              <bitWidth>2</bitWidth>
            </field>
            <field>
              <name>PUPD8</name>
              <bitOffset>16</bitOffset>
              <bitWidth>2</bitWidth>
            </field>
            <field>
              <name>PUPD9</name>
              <bitOffset>18</bitOffset>
              <bitWidth>2</bitWidth>
            </field>
            <field>
              <name>PUPD10</name>
              <bitOffset>20</bitOffset>
              <bitWidth>2</bitWidth>
            </field>
            <field>
              <name>PUPD11</name>
              <bitOffset>22</bitOffset>
              <bitWidth>2</bitWidth>
            </field>
            <field>
              <name>PUPD12</name>
              <bitOffset>24</bitOffset>
              <bitWidth>2</bitWidth>
            </field>
            <field>
              <name>PUPD13</name>
              <bitOffset>26</bitOffset>
              <bitWidth>2</bitWidth>
            </field>
            <field>
              <name>PUPD14</name>
              <bitOffset>28</bitOffset>
              <bitWidth>2</bitWidth>
            </field>
            <field>
              <name>PUPD15</name>
              <bitOffset>30</bitOffset>
              <bitWidth>2</bitWidth>
            </field>
          </fields>
        </register>
        <register>
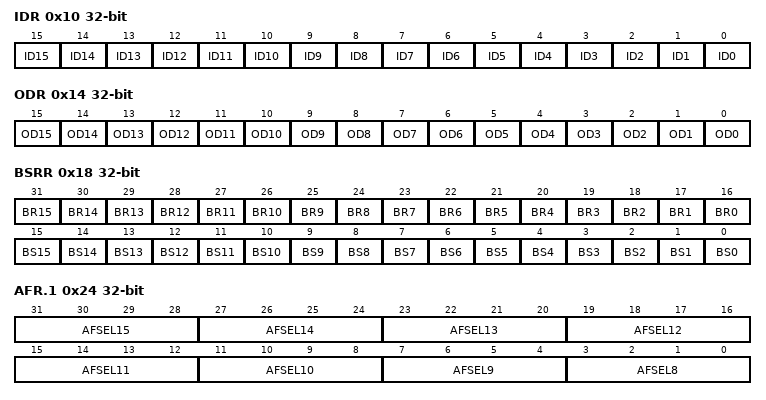
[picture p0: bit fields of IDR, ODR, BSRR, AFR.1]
          <name>IDR</name>
          <addressOffset>0x10</addressOffset>
          <size>0x20</size>
          <fields>
            <field>
              <name>ID0</name>
              <bitOffset>0</bitOffset>
              <bitWidth>1</bitWidth>
            </field>
            <field>
              <name>ID1</name>
              <bitOffset>1</bitOffset>
              <bitWidth>1</bitWidth>
            </field>
            <field>
              <name>ID2</name>
              <bitOffset>2</bitOffset>
              <bitWidth>1</bitWidth>
            </field>
            <field>
              <name>ID3</name>
              <bitOffset>3</bitOffset>
              <bitWidth>1</bitWidth>
            </field>
            <field>
              <name>ID4</name>
              <bitOffset>4</bitOffset>
              <bitWidth>1</bitWidth>
            </field>
            <field>
              <name>ID5</name>
              <bitOffset>5</bitOffset>
              <bitWidth>1</bitWidth>
            </field>
            <field>
              <name>ID6</name>
              <bitOffset>6</bitOffset>
              <bitWidth>1</bitWidth>
            </field>
            <field>
              <name>ID7</name>
              <bitOffset>7</bitOffset>
              <bitWidth>1</bitWidth>
            </field>
            <field>
              <name>ID8</name>
              <bitOffset>8</bitOffset>
              <bitWidth>1</bitWidth>
            </field>
            <field>
              <name>ID9</name>
              <bitOffset>9</bitOffset>
              <bitWidth>1</bitWidth>
            </field>
            <field>
              <name>ID10</name>
              <bitOffset>10</bitOffset>
              <bitWidth>1</bitWidth>
            </field>
            <field>
              <name>ID11</name>
              <bitOffset>11</bitOffset>
              <bitWidth>1</bitWidth>
            </field>
            <field>
              <name>ID12</name>
              <bitOffset>12</bitOffset>
              <bitWidth>1</bitWidth>
            </field>
            <field>
              <name>ID13</name>
              <bitOffset>13</bitOffset>
              <bitWidth>1</bitWidth>
            </field>
            <field>
              <name>ID14</name>
              <bitOffset>14</bitOffset>
              <bitWidth>1</bitWidth>
            </field>
            <field>
              <name>ID15</name>
              <bitOffset>15</bitOffset>
              <bitWidth>1</bitWidth>
            </field>
          </fields>
        </register>
        <register>
          <name>ODR</name>
          <addressOffset>0x14</addressOffset>
          <size>0x20</size>
          <fields>
            <field>
              <name>OD0</name>
              <bitOffset>0</bitOffset>
              <bitWidth>1</bitWidth>
            </field>
            <field>
              <name>OD1</name>
              <bitOffset>1</bitOffset>
              <bitWidth>1</bitWidth>
            </field>
            <field>
              <name>OD2</name>
              <bitOffset>2</bitOffset>
              <bitWidth>1</bitWidth>
            </field>
            <field>
              <name>OD3</name>
              <bitOffset>3</bitOffset>
              <bitWidth>1</bitWidth>
            </field>
            <field>
              <name>OD4</name>
              <bitOffset>4</bitOffset>
              <bitWidth>1</bitWidth>
            </field>
            <field>
              <name>OD5</name>
              <bitOffset>5</bitOffset>
              <bitWidth>1</bitWidth>
            </field>
            <field>
              <name>OD6</name>
              <bitOffset>6</bitOffset>
              <bitWidth>1</bitWidth>
            </field>
            <field>
              <name>OD7</name>
              <bitOffset>7</bitOffset>
              <bitWidth>1</bitWidth>
            </field>
            <field>
              <name>OD8</name>
              <bitOffset>8</bitOffset>
              <bitWidth>1</bitWidth>
            </field>
            <field>
              <name>OD9</name>
              <bitOffset>9</bitOffset>
              <bitWidth>1</bitWidth>
            </field>
            <field>
              <name>OD10</name>
              <bitOffset>10</bitOffset>
              <bitWidth>1</bitWidth>
            </field>
            <field>
              <name>OD11</name>
              <bitOffset>11</bitOffset>
              <bitWidth>1</bitWidth>
            </field>
            <field>
              <name>OD12</name>
              <bitOffset>12</bitOffset>
              <bitWidth>1</bitWidth>
            </field>
            <field>
              <name>OD13</name>
              <bitOffset>13</bitOffset>
              <bitWidth>1</bitWidth>
            </field>
            <field>
              <name>OD14</name>
              <bitOffset>14</bitOffset>
              <bitWidth>1</bitWidth>
            </field>
            <field>
              <name>OD15</name>
              <bitOffset>15</bitOffset>
              <bitWidth>1</bitWidth>
            </field>
          </fields>
        </register>
        <register>
          <name>BSRR</name>
          <addressOffset>0x18</addressOffset>
          <size>0x20</size>
          <fields>
            <field>
              <name>BS0</name>
              <bitOffset>0</bitOffset>
              <bitWidth>1</bitWidth>
            </field>
            <field>
              <name>BS1</name>
              <bitOffset>1</bitOffset>
              <bitWidth>1</bitWidth>
            </field>
            <field>
              <name>BS2</name>
              <bitOffset>2</bitOffset>
              <bitWidth>1</bitWidth>
            </field>
            <field>
              <name>BS3</name>
              <bitOffset>3</bitOffset>
              <bitWidth>1</bitWidth>
            </field>
            <field>
              <name>BS4</name>
              <bitOffset>4</bitOffset>
              <bitWidth>1</bitWidth>
            </field>
            <field>
              <name>BS5</name>
              <bitOffset>5</bitOffset>
              <bitWidth>1</bitWidth>
            </field>
            <field>
              <name>BS6</name>
              <bitOffset>6</bitOffset>
              <bitWidth>1</bitWidth>
            </field>
            <field>
              <name>BS7</name>
              <bitOffset>7</bitOffset>
              <bitWidth>1</bitWidth>
            </field>
            <field>
              <name>BS8</name>
              <bitOffset>8</bitOffset>
              <bitWidth>1</bitWidth>
            </field>
            <field>
              <name>BS9</name>
              <bitOffset>9</bitOffset>
              <bitWidth>1</bitWidth>
            </field>
            <field>
              <name>BS10</name>
              <bitOffset>10</bitOffset>
              <bitWidth>1</bitWidth>
            </field>
            <field>
              <name>BS11</name>
              <bitOffset>11</bitOffset>
              <bitWidth>1</bitWidth>
            </field>
            <field>
              <name>BS12</name>
              <bitOffset>12</bitOffset>
              <bitWidth>1</bitWidth>
            </field>
            <field>
              <name>BS13</name>
              <bitOffset>13</bitOffset>
              <bitWidth>1</bitWidth>
            </field>
            <field>
              <name>BS14</name>
              <bitOffset>14</bitOffset>
              <bitWidth>1</bitWidth>
            </field>
            <field>
              <name>BS15</name>
              <bitOffset>15</bitOffset>
              <bitWidth>1</bitWidth>
            </field>
            <field>
              <name>BR0</name>
              <bitOffset>16</bitOffset>
              <bitWidth>1</bitWidth>
            </field>
            <field>
              <name>BR1</name>
              <bitOffset>17</bitOffset>
              <bitWidth>1</bitWidth>
            </field>
            <field>
              <name>BR2</name>
              <bitOffset>18</bitOffset>
              <bitWidth>1</bitWidth>
            </field>
            <field>
              <name>BR3</name>
              <bitOffset>19</bitOffset>
              <bitWidth>1</bitWidth>
            </field>
            <field>
              <name>BR4</name>
              <bitOffset>20</bitOffset>
              <bitWidth>1</bitWidth>
            </field>
            <field>
              <name>BR5</name>
              <bitOffset>21</bitOffset>
              <bitWidth>1</bitWidth>
            </field>
            <field>
              <name>BR6</name>
              <bitOffset>22</bitOffset>
              <bitWidth>1</bitWidth>
            </field>
            <field>
              <name>BR7</name>
              <bitOffset>23</bitOffset>
              <bitWidth>1</bitWidth>
            </field>
            <field>
              <name>BR8</name>
              <bitOffset>24</bitOffset>
              <bitWidth>1</bitWidth>
            </field>
            <field>
              <name>BR9</name>
              <bitOffset>25</bitOffset>
              <bitWidth>1</bitWidth>
            </field>
            <field>
              <name>BR10</name>
              <bitOffset>26</bitOffset>
              <bitWidth>1</bitWidth>
            </field>
            <field>
              <name>BR11</name>
              <bitOffset>27</bitOffset>
              <bitWidth>1</bitWidth>
            </field>
            <field>
              <name>BR12</name>
              <bitOffset>28</bitOffset>
              <bitWidth>1</bitWidth>
            </field>
            <field>
              <name>BR13</name>
              <bitOffset>29</bitOffset>
              <bitWidth>1</bitWidth>
            </field>
            <field>
              <name>BR14</name>
              <bitOffset>30</bitOffset>
              <bitWidth>1</bitWidth>
            </field>
            <field>
              <name>BR15</name>
              <bitOffset>31</bitOffset>
              <bitWidth>1</bitWidth>
            </field>
          </fields>
        </register>
        <register>
          <name>LCKR</name>
          <addressOffset>0x1c</addressOffset>
          <size>0x20</size>
        </register>
        <register>
          <name>AFR.0</name>
          <addressOffset>0x20</addressOffset>
          <size>0x20</size>
        </register>
        <register>
          <name>AFR.1</name>
          <addressOffset>0x24</addressOffset>
          <size>0x20</size>
          <fields>
            <field>
              <name>AFSEL8</name>
              <bitOffset>0</bitOffset>
              <bitWidth>4</bitWidth>
            </field>
            <field>
              <name>AFSEL9</name>
              <bitOffset>4</bitOffset>
              <bitWidth>4</bitWidth>
            </field>
            <field>
              <name>AFSEL10</name>
              <bitOffset>8</bitOffset>
              <bitWidth>4</bitWidth>
            </field>
            <field>
              <name>AFSEL11</name>
              <bitOffset>12</bitOffset>
              <bitWidth>4</bitWidth>
            </field>
            <field>
              <name>AFSEL12</name>
              <bitOffset>16</bitOffset>
              <bitWidth>4</bitWidth>
            </field>
            <field>
              <name>AFSEL13</name>
              <bitOffset>20</bitOffset>
              <bitWidth>4</bitWidth>
            </field>
            <field>
              <name>AFSEL14</name>
              <bitOffset>24</bitOffset>
              <bitWidth>4</bitWidth>
            </field>
            <field>
              <name>AFSEL15</name>
              <bitOffset>28</bitOffset>
              <bitWidth>4</bitWidth>
            </field>
          </fields>
        </register>
      </registers>
    </peripheral>
    <peripheral>
      <name>GPIOH</name>
      <baseAddress>0x40021c00</baseAddress>
      <registers>
        <register>
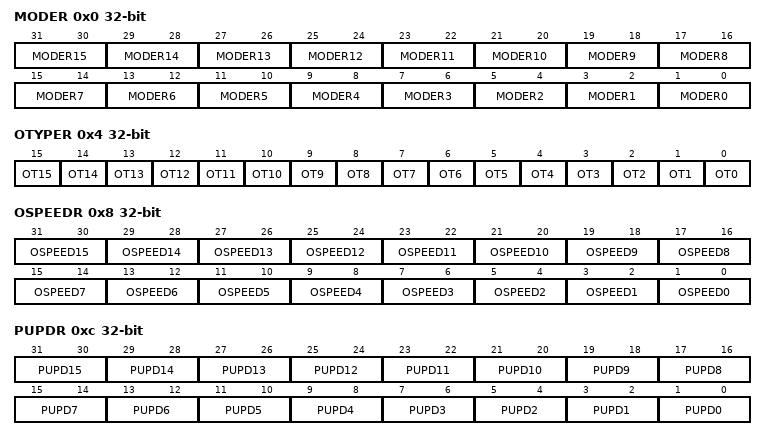
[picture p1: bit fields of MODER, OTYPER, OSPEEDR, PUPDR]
          <name>MODER</name>
          <addressOffset>0x0</addressOffset>
          <size>0x20</size>
          <fields>
            <field>
              <name>MODER0</name>
              <bitOffset>0</bitOffset>
              <bitWidth>2</bitWidth>
            </field>
            <field>
              <name>MODER1</name>
              <bitOffset>2</bitOffset>
              <bitWidth>2</bitWidth>
            </field>
            <field>
              <name>MODER2</name>
              <bitOffset>4</bitOffset>
              <bitWidth>2</bitWidth>
            </field>
            <field>
              <name>MODER3</name>
              <bitOffset>6</bitOffset>
              <bitWidth>2</bitWidth>
            </field>
            <field>
              <name>MODER4</name>
              <bitOffset>8</bitOffset>
              <bitWidth>2</bitWidth>
            </field>
            <field>
              <name>MODER5</name>
              <bitOffset>10</bitOffset>
              <bitWidth>2</bitWidth>
            </field>
            <field>
              <name>MODER6</name>
              <bitOffset>12</bitOffset>
              <bitWidth>2</bitWidth>
            </field>
            <field>
              <name>MODER7</name>
              <bitOffset>14</bitOffset>
              <bitWidth>2</bitWidth>
            </field>
            <field>
              <name>MODER8</name>
              <bitOffset>16</bitOffset>
              <bitWidth>2</bitWidth>
            </field>
            <field>
              <name>MODER9</name>
              <bitOffset>18</bitOffset>
              <bitWidth>2</bitWidth>
            </field>
            <field>
              <name>MODER10</name>
              <bitOffset>20</bitOffset>
              <bitWidth>2</bitWidth>
            </field>
            <field>
              <name>MODER11</name>
              <bitOffset>22</bitOffset>
              <bitWidth>2</bitWidth>
            </field>
            <field>
              <name>MODER12</name>
              <bitOffset>24</bitOffset>
              <bitWidth>2</bitWidth>
            </field>
            <field>
              <name>MODER13</name>
              <bitOffset>26</bitOffset>
              <bitWidth>2</bitWidth>
            </field>
            <field>
              <name>MODER14</name>
              <bitOffset>28</bitOffset>
              <bitWidth>2</bitWidth>
            </field>
            <field>
              <name>MODER15</name>
              <bitOffset>30</bitOffset>
              <bitWidth>2</bitWidth>
            </field>
          </fields>
        </register>
        <register>
          <name>OTYPER</name>
          <addressOffset>0x4</addressOffset>
          <size>0x20</size>
          <fields>
            <field>
              <name>OT0</name>
              <bitOffset>0</bitOffset>
              <bitWidth>1</bitWidth>
            </field>
            <field>
              <name>OT1</name>
              <bitOffset>1</bitOffset>
              <bitWidth>1</bitWidth>
            </field>
            <field>
              <name>OT2</name>
              <bitOffset>2</bitOffset>
              <bitWidth>1</bitWidth>
            </field>
            <field>
              <name>OT3</name>
              <bitOffset>3</bitOffset>
              <bitWidth>1</bitWidth>
            </field>
            <field>
              <name>OT4</name>
              <bitOffset>4</bitOffset>
              <bitWidth>1</bitWidth>
            </field>
            <field>
              <name>OT5</name>
              <bitOffset>5</bitOffset>
              <bitWidth>1</bitWidth>
            </field>
            <field>
              <name>OT6</name>
              <bitOffset>6</bitOffset>
              <bitWidth>1</bitWidth>
            </field>
            <field>
              <name>OT7</name>
              <bitOffset>7</bitOffset>
              <bitWidth>1</bitWidth>
            </field>
            <field>
              <name>OT8</name>
              <bitOffset>8</bitOffset>
              <bitWidth>1</bitWidth>
            </field>
            <field>
              <name>OT9</name>
              <bitOffset>9</bitOffset>
              <bitWidth>1</bitWidth>
            </field>
            <field>
              <name>OT10</name>
              <bitOffset>10</bitOffset>
              <bitWidth>1</bitWidth>
            </field>
            <field>
              <name>OT11</name>
              <bitOffset>11</bitOffset>
              <bitWidth>1</bitWidth>
            </field>
            <field>
              <name>OT12</name>
              <bitOffset>12</bitOffset>
              <bitWidth>1</bitWidth>
            </field>
            <field>
              <name>OT13</name>
              <bitOffset>13</bitOffset>
              <bitWidth>1</bitWidth>
            </field>
            <field>
              <name>OT14</name>
              <bitOffset>14</bitOffset>
              <bitWidth>1</bitWidth>
            </field>
            <field>
              <name>OT15</name>
              <bitOffset>15</bitOffset>
              <bitWidth>1</bitWidth>
            </field>
          </fields>
        </register>
        <register>
          <name>OSPEEDR</name>
          <addressOffset>0x8</addressOffset>
          <size>0x20</size>
          <fields>
            <field>
              <name>OSPEED0</name>
              <bitOffset>0</bitOffset>
              <bitWidth>2</bitWidth>
            </field>
            <field>
              <name>OSPEED1</name>
              <bitOffset>2</bitOffset>
              <bitWidth>2</bitWidth>
            </field>
            <field>
              <name>OSPEED2</name>
              <bitOffset>4</bitOffset>
              <bitWidth>2</bitWidth>
            </field>
            <field>
              <name>OSPEED3</name>
              <bitOffset>6</bitOffset>
              <bitWidth>2</bitWidth>
            </field>
            <field>
              <name>OSPEED4</name>
              <bitOffset>8</bitOffset>
              <bitWidth>2</bitWidth>
            </field>
            <field>
              <name>OSPEED5</name>
              <bitOffset>10</bitOffset>
              <bitWidth>2</bitWidth>
            </field>
            <field>
              <name>OSPEED6</name>
              <bitOffset>12</bitOffset>
              <bitWidth>2</bitWidth>
            </field>
            <field>
              <name>OSPEED7</name>
              <bitOffset>14</bitOffset>
              <bitWidth>2</bitWidth>
            </field>
            <field>
              <name>OSPEED8</name>
              <bitOffset>16</bitOffset>
              <bitWidth>2</bitWidth>
            </field>
            <field>
              <name>OSPEED9</name>
              <bitOffset>18</bitOffset>
              <bitWidth>2</bitWidth>
            </field>
            <field>
              <name>OSPEED10</name>
              <bitOffset>20</bitOffset>
              <bitWidth>2</bitWidth>
            </field>
            <field>
              <name>OSPEED11</name>
              <bitOffset>22</bitOffset>
              <bitWidth>2</bitWidth>
            </field>
            <field>
              <name>OSPEED12</name>
              <bitOffset>24</bitOffset>
              <bitWidth>2</bitWidth>
            </field>
            <field>
              <name>OSPEED13</name>
              <bitOffset>26</bitOffset>
              <bitWidth>2</bitWidth>
            </field>
            <field>
              <name>OSPEED14</name>
              <bitOffset>28</bitOffset>
              <bitWidth>2</bitWidth>
            </field>
            <field>
              <name>OSPEED15</name>
              <bitOffset>30</bitOffset>
              <bitWidth>2</bitWidth>
            </field>
          </fields>
        </register>
        <register>
          <name>PUPDR</name>
          <addressOffset>0xc</addressOffset>
          <size>0x20</size>
          <fields>
            <field>
              <name>PUPD0</name>
              <bitOffset>0</bitOffset>
              <bitWidth>2</bitWidth>
            </field>
            <field>
              <name>PUPD1</name>
              <bitOffset>2</bitOffset>
              <bitWidth>2</bitWidth>
            </field>
            <field>
              <name>PUPD2</name>
              <bitOffset>4</bitOffset>
              <bitWidth>2</bitWidth>
            </field>
            <field>
              <name>PUPD3</name>
              <bitOffset>6</bitOffset>
              <bitWidth>2</bitWidth>
            </field>
            <field>
              <name>PUPD4</name>
              <bitOffset>8</bitOffset>
              <bitWidth>2</bitWidth>
            </field>
            <field>
              <name>PUPD5</name>
              <bitOffset>10</bitOffset>
              <bitWidth>2</bitWidth>
            </field>
            <field>
              <name>PUPD6</name>
              <bitOffset>12</bitOffset>
              <bitWidth>2</bitWidth>
            </field>
            <field>
              <name>PUPD7</name>
              <bitOffset>14</bitOffset>
              <bitWidth>2</bitWidth>
            </field>
            <field>
              <name>PUPD8</name>
              <bitOffset>16</bitOffset>
              <bitWidth>2</bitWidth>
            </field>
            <field>
              <name>PUPD9</name>
              <bitOffset>18</bitOffset>
              <bitWidth>2</bitWidth>
            </field>
            <field>
              <name>PUPD10</name>
              <bitOffset>20</bitOffset>
              <bitWidth>2</bitWidth>
            </field>
            <field>
              <name>PUPD11</name>
              <bitOffset>22</bitOffset>
              <bitWidth>2</bitWidth>
            </field>
            <field>
              <name>PUPD12</name>
              <bitOffset>24</bitOffset>
              <bitWidth>2</bitWidth>
            </field>
            <field>
              <name>PUPD13</name>
              <bitOffset>26</bitOffset>
              <bitWidth>2</bitWidth>
            </field>
            <field>
              <name>PUPD14</name>
              <bitOffset>28</bitOffset>
              <bitWidth>2</bitWidth>
            </field>
            <field>
              <name>PUPD15</name>
              <bitOffset>30</bitOffset>
              <bitWidth>2</bitWidth>
            </field>
          </fields>
        </register>
        <register>
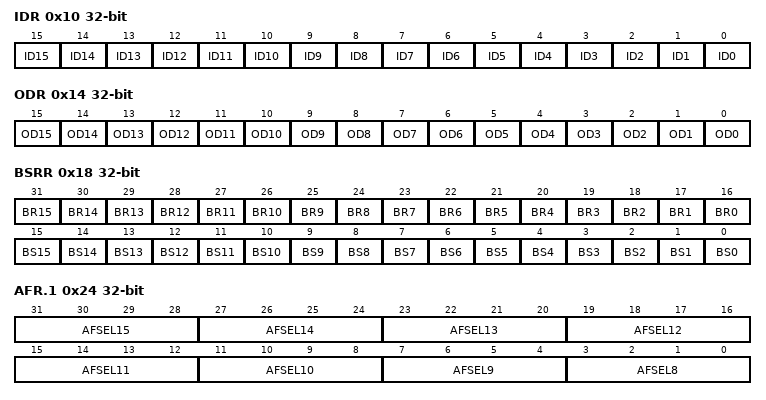
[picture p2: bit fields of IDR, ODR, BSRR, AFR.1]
          <name>IDR</name>
          <addressOffset>0x10</addressOffset>
          <size>0x20</size>
          <fields>
            <field>
              <name>ID0</name>
              <bitOffset>0</bitOffset>
              <bitWidth>1</bitWidth>
            </field>
            <field>
              <name>ID1</name>
              <bitOffset>1</bitOffset>
              <bitWidth>1</bitWidth>
            </field>
            <field>
              <name>ID2</name>
              <bitOffset>2</bitOffset>
              <bitWidth>1</bitWidth>
            </field>
            <field>
              <name>ID3</name>
              <bitOffset>3</bitOffset>
              <bitWidth>1</bitWidth>
            </field>
            <field>
              <name>ID4</name>
              <bitOffset>4</bitOffset>
              <bitWidth>1</bitWidth>
            </field>
            <field>
              <name>ID5</name>
              <bitOffset>5</bitOffset>
              <bitWidth>1</bitWidth>
            </field>
            <field>
              <name>ID6</name>
              <bitOffset>6</bitOffset>
              <bitWidth>1</bitWidth>
            </field>
            <field>
              <name>ID7</name>
              <bitOffset>7</bitOffset>
              <bitWidth>1</bitWidth>
            </field>
            <field>
              <name>ID8</name>
              <bitOffset>8</bitOffset>
              <bitWidth>1</bitWidth>
            </field>
            <field>
              <name>ID9</name>
              <bitOffset>9</bitOffset>
              <bitWidth>1</bitWidth>
            </field>
            <field>
              <name>ID10</name>
              <bitOffset>10</bitOffset>
              <bitWidth>1</bitWidth>
            </field>
            <field>
              <name>ID11</name>
              <bitOffset>11</bitOffset>
              <bitWidth>1</bitWidth>
            </field>
            <field>
              <name>ID12</name>
              <bitOffset>12</bitOffset>
              <bitWidth>1</bitWidth>
            </field>
            <field>
              <name>ID13</name>
              <bitOffset>13</bitOffset>
              <bitWidth>1</bitWidth>
            </field>
            <field>
              <name>ID14</name>
              <bitOffset>14</bitOffset>
              <bitWidth>1</bitWidth>
            </field>
            <field>
              <name>ID15</name>
              <bitOffset>15</bitOffset>
              <bitWidth>1</bitWidth>
            </field>
          </fields>
        </register>
        <register>
          <name>ODR</name>
          <addressOffset>0x14</addressOffset>
          <size>0x20</size>
          <fields>
            <field>
              <name>OD0</name>
              <bitOffset>0</bitOffset>
              <bitWidth>1</bitWidth>
            </field>
            <field>
              <name>OD1</name>
              <bitOffset>1</bitOffset>
              <bitWidth>1</bitWidth>
            </field>
            <field>
              <name>OD2</name>
              <bitOffset>2</bitOffset>
              <bitWidth>1</bitWidth>
            </field>
            <field>
              <name>OD3</name>
              <bitOffset>3</bitOffset>
              <bitWidth>1</bitWidth>
            </field>
            <field>
              <name>OD4</name>
              <bitOffset>4</bitOffset>
              <bitWidth>1</bitWidth>
            </field>
            <field>
              <name>OD5</name>
              <bitOffset>5</bitOffset>
              <bitWidth>1</bitWidth>
            </field>
            <field>
              <name>OD6</name>
              <bitOffset>6</bitOffset>
              <bitWidth>1</bitWidth>
            </field>
            <field>
              <name>OD7</name>
              <bitOffset>7</bitOffset>
              <bitWidth>1</bitWidth>
            </field>
            <field>
              <name>OD8</name>
              <bitOffset>8</bitOffset>
              <bitWidth>1</bitWidth>
            </field>
            <field>
              <name>OD9</name>
              <bitOffset>9</bitOffset>
              <bitWidth>1</bitWidth>
            </field>
            <field>
              <name>OD10</name>
              <bitOffset>10</bitOffset>
              <bitWidth>1</bitWidth>
            </field>
            <field>
              <name>OD11</name>
              <bitOffset>11</bitOffset>
              <bitWidth>1</bitWidth>
            </field>
            <field>
              <name>OD12</name>
              <bitOffset>12</bitOffset>
              <bitWidth>1</bitWidth>
            </field>
            <field>
              <name>OD13</name>
              <bitOffset>13</bitOffset>
              <bitWidth>1</bitWidth>
            </field>
            <field>
              <name>OD14</name>
              <bitOffset>14</bitOffset>
              <bitWidth>1</bitWidth>
            </field>
            <field>
              <name>OD15</name>
              <bitOffset>15</bitOffset>
              <bitWidth>1</bitWidth>
            </field>
          </fields>
        </register>
        <register>
          <name>BSRR</name>
          <addressOffset>0x18</addressOffset>
          <size>0x20</size>
          <fields>
            <field>
              <name>BS0</name>
              <bitOffset>0</bitOffset>
              <bitWidth>1</bitWidth>
            </field>
            <field>
              <name>BS1</name>
              <bitOffset>1</bitOffset>
              <bitWidth>1</bitWidth>
            </field>
            <field>
              <name>BS2</name>
              <bitOffset>2</bitOffset>
              <bitWidth>1</bitWidth>
            </field>
            <field>
              <name>BS3</name>
              <bitOffset>3</bitOffset>
              <bitWidth>1</bitWidth>
            </field>
            <field>
              <name>BS4</name>
              <bitOffset>4</bitOffset>
              <bitWidth>1</bitWidth>
            </field>
            <field>
              <name>BS5</name>
              <bitOffset>5</bitOffset>
              <bitWidth>1</bitWidth>
            </field>
            <field>
              <name>BS6</name>
              <bitOffset>6</bitOffset>
              <bitWidth>1</bitWidth>
            </field>
            <field>
              <name>BS7</name>
              <bitOffset>7</bitOffset>
              <bitWidth>1</bitWidth>
            </field>
            <field>
              <name>BS8</name>
              <bitOffset>8</bitOffset>
              <bitWidth>1</bitWidth>
            </field>
            <field>
              <name>BS9</name>
              <bitOffset>9</bitOffset>
              <bitWidth>1</bitWidth>
            </field>
            <field>
              <name>BS10</name>
              <bitOffset>10</bitOffset>
              <bitWidth>1</bitWidth>
            </field>
            <field>
              <name>BS11</name>
              <bitOffset>11</bitOffset>
              <bitWidth>1</bitWidth>
            </field>
            <field>
              <name>BS12</name>
              <bitOffset>12</bitOffset>
              <bitWidth>1</bitWidth>
            </field>
            <field>
              <name>BS13</name>
              <bitOffset>13</bitOffset>
              <bitWidth>1</bitWidth>
            </field>
            <field>
              <name>BS14</name>
              <bitOffset>14</bitOffset>
              <bitWidth>1</bitWidth>
            </field>
            <field>
              <name>BS15</name>
              <bitOffset>15</bitOffset>
              <bitWidth>1</bitWidth>
            </field>
            <field>
              <name>BR0</name>
              <bitOffset>16</bitOffset>
              <bitWidth>1</bitWidth>
            </field>
            <field>
              <name>BR1</name>
              <bitOffset>17</bitOffset>
              <bitWidth>1</bitWidth>
            </field>
            <field>
              <name>BR2</name>
              <bitOffset>18</bitOffset>
              <bitWidth>1</bitWidth>
            </field>
            <field>
              <name>BR3</name>
              <bitOffset>19</bitOffset>
              <bitWidth>1</bitWidth>
            </field>
            <field>
              <name>BR4</name>
              <bitOffset>20</bitOffset>
              <bitWidth>1</bitWidth>
            </field>
            <field>
              <name>BR5</name>
              <bitOffset>21</bitOffset>
              <bitWidth>1</bitWidth>
            </field>
            <field>
              <name>BR6</name>
              <bitOffset>22</bitOffset>
              <bitWidth>1</bitWidth>
            </field>
            <field>
              <name>BR7</name>
              <bitOffset>23</bitOffset>
              <bitWidth>1</bitWidth>
            </field>
            <field>
              <name>BR8</name>
              <bitOffset>24</bitOffset>
              <bitWidth>1</bitWidth>
            </field>
            <field>
              <name>BR9</name>
              <bitOffset>25</bitOffset>
              <bitWidth>1</bitWidth>
            </field>
            <field>
              <name>BR10</name>
              <bitOffset>26</bitOffset>
              <bitWidth>1</bitWidth>
            </field>
            <field>
              <name>BR11</name>
              <bitOffset>27</bitOffset>
              <bitWidth>1</bitWidth>
            </field>
            <field>
              <name>BR12</name>
              <bitOffset>28</bitOffset>
              <bitWidth>1</bitWidth>
            </field>
            <field>
              <name>BR13</name>
              <bitOffset>29</bitOffset>
              <bitWidth>1</bitWidth>
            </field>
            <field>
              <name>BR14</name>
              <bitOffset>30</bitOffset>
              <bitWidth>1</bitWidth>
            </field>
            <field>
              <name>BR15</name>
              <bitOffset>31</bitOffset>
              <bitWidth>1</bitWidth>
            </field>
          </fields>
        </register>
        <register>
          <name>LCKR</name>
          <addressOffset>0x1c</addressOffset>
          <size>0x20</size>
        </register>
        <register>
          <name>AFR.0</name>
          <addressOffset>0x20</addressOffset>
          <size>0x20</size>
        </register>
        <register>
          <name>AFR.1</name>
          <addressOffset>0x24</addressOffset>
          <size>0x20</size>
          <fields>
            <field>
              <name>AFSEL8</name>
              <bitOffset>0</bitOffset>
              <bitWidth>4</bitWidth>
            </field>
            <field>
              <name>AFSEL9</name>
              <bitOffset>4</bitOffset>
              <bitWidth>4</bitWidth>
            </field>
            <field>
              <name>AFSEL10</name>
              <bitOffset>8</bitOffset>
              <bitWidth>4</bitWidth>
            </field>
            <field>
              <name>AFSEL11</name>
              <bitOffset>12</bitOffset>
              <bitWidth>4</bitWidth>
            </field>
            <field>
              <name>AFSEL12</name>
              <bitOffset>16</bitOffset>
              <bitWidth>4</bitWidth>
            </field>
            <field>
              <name>AFSEL13</name>
              <bitOffset>20</bitOffset>
              <bitWidth>4</bitWidth>
            </field>
            <field>
              <name>AFSEL14</name>
              <bitOffset>24</bitOffset>
              <bitWidth>4</bitWidth>
            </field>
            <field>
              <name>AFSEL15</name>
              <bitOffset>28</bitOffset>
              <bitWidth>4</bitWidth>
            </field>
          </fields>
        </register>
      </registers>
    </peripheral>
    <peripheral>
      <name>CRC</name>
      <baseAddress>0x40023000</baseAddress>
      <registers>
        <register>
          <name>DR</name>
          <addressOffset>0x0</addressOffset>
          <size>0x20</size>
          <fields>
            <field>
              <name>DR</name>
              <bitOffset>0</bitOffset>
              <bitWidth>32</bitWidth>
            </field>
          </fields>
        </register>
        <register>
          <name>IDR</name>
          <addressOffset>0x4</addressOffset>
          <size>0x8</size>
          <fields>
            <field>
              <name>IDR</name>
              <bitOffset>0</bitOffset>
              <bitWidth>8</bitWidth>
            </field>
          </fields>
        </register>
        <register>
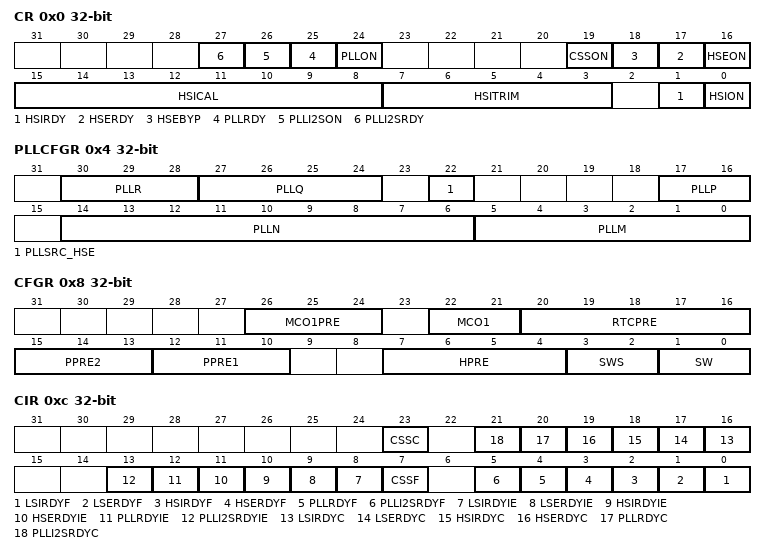
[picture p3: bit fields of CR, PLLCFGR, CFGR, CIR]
          <name>CR</name>
          <addressOffset>0x8</addressOffset>
          <size>0x20</size>
          <fields>
            <field>
              <name>RESET</name>
              <bitOffset>0</bitOffset>
              <bitWidth>1</bitWidth>
            </field>
          </fields>
        </register>
      </registers>
    </peripheral>
    <peripheral>
      <name>RCC</name>
      <baseAddress>0x40023800</baseAddress>
      <registers>
        <register>
          <name>CR</name>
          <addressOffset>0x0</addressOffset>
          <size>0x20</size>
          <fields>
            <field>
              <name>HSION</name>
              <bitOffset>0</bitOffset>
              <bitWidth>1</bitWidth>
            </field>
            <field>
              <name>HSIRDY</name>
              <bitOffset>1</bitOffset>
              <bitWidth>1</bitWidth>
            </field>
            <field>
              <name>HSITRIM</name>
              <bitOffset>3</bitOffset>
              <bitWidth>5</bitWidth>
            </field>
            <field>
              <name>HSICAL</name>
              <bitOffset>8</bitOffset>
              <bitWidth>8</bitWidth>
            </field>
            <field>
              <name>HSEON</name>
              <bitOffset>16</bitOffset>
              <bitWidth>1</bitWidth>
            </field>
            <field>
              <name>HSERDY</name>
              <bitOffset>17</bitOffset>
              <bitWidth>1</bitWidth>
            </field>
            <field>
              <name>HSEBYP</name>
              <bitOffset>18</bitOffset>
              <bitWidth>1</bitWidth>
            </field>
            <field>
              <name>CSSON</name>
              <bitOffset>19</bitOffset>
              <bitWidth>1</bitWidth>
            </field>
            <field>
              <name>PLLON</name>
              <bitOffset>24</bitOffset>
              <bitWidth>1</bitWidth>
            </field>
            <field>
              <name>PLLRDY</name>
              <bitOffset>25</bitOffset>
              <bitWidth>1</bitWidth>
            </field>
            <field>
              <name>PLLI2SON</name>
              <bitOffset>26</bitOffset>
              <bitWidth>1</bitWidth>
            </field>
            <field>
              <name>PLLI2SRDY</name>
              <bitOffset>27</bitOffset>
              <bitWidth>1</bitWidth>
            </field>
          </fields>
        </register>
        <register>
          <name>PLLCFGR</name>
          <addressOffset>0x4</addressOffset>
          <size>0x20</size>
          <fields>
            <field>
              <name>PLLM</name>
              <bitOffset>0</bitOffset>
              <bitWidth>6</bitWidth>
            </field>
            <field>
              <name>PLLN</name>
              <bitOffset>6</bitOffset>
              <bitWidth>9</bitWidth>
            </field>
            <field>
              <name>PLLP</name>
              <bitOffset>16</bitOffset>
              <bitWidth>2</bitWidth>
            </field>
            <field>
              <name>PLLSRC_HSE</name>
              <bitOffset>22</bitOffset>
              <bitWidth>1</bitWidth>
            </field>
            <field>
              <name>PLLQ</name>
              <bitOffset>24</bitOffset>
              <bitWidth>4</bitWidth>
            </field>
            <field>
              <name>PLLR</name>
              <bitOffset>28</bitOffset>
              <bitWidth>3</bitWidth>
            </field>
          </fields>
        </register>
        <register>
          <name>CFGR</name>
          <addressOffset>0x8</addressOffset>
          <size>0x20</size>
          <fields>
            <field>
              <name>SW</name>
              <bitOffset>0</bitOffset>
              <bitWidth>2</bitWidth>
            </field>
            <field>
              <name>SWS</name>
              <bitOffset>2</bitOffset>
              <bitWidth>2</bitWidth>
            </field>
            <field>
              <name>HPRE</name>
              <bitOffset>4</bitOffset>
              <bitWidth>4</bitWidth>
            </field>
            <field>
              <name>PPRE1</name>
              <bitOffset>10</bitOffset>
              <bitWidth>3</bitWidth>
            </field>
            <field>
              <name>PPRE2</name>
              <bitOffset>13</bitOffset>
              <bitWidth>3</bitWidth>
            </field>
            <field>
              <name>RTCPRE</name>
              <bitOffset>16</bitOffset>
              <bitWidth>5</bitWidth>
            </field>
            <field>
              <name>MCO1</name>
              <bitOffset>21</bitOffset>
              <bitWidth>2</bitWidth>
            </field>
            <field>
              <name>MCO1PRE</name>
              <bitOffset>24</bitOffset>
              <bitWidth>3</bitWidth>
            </field>
          </fields>
        </register>
        <register>
          <name>CIR</name>
          <addressOffset>0xc</addressOffset>
          <size>0x20</size>
          <fields>
            <field>
              <name>LSIRDYF</name>
              <bitOffset>0</bitOffset>
              <bitWidth>1</bitWidth>
            </field>
            <field>
              <name>LSERDYF</name>
              <bitOffset>1</bitOffset>
              <bitWidth>1</bitWidth>
            </field>
            <field>
              <name>HSIRDYF</name>
              <bitOffset>2</bitOffset>
              <bitWidth>1</bitWidth>
            </field>
            <field>
              <name>HSERDYF</name>
              <bitOffset>3</bitOffset>
              <bitWidth>1</bitWidth>
            </field>
            <field>
              <name>PLLRDYF</name>
              <bitOffset>4</bitOffset>
              <bitWidth>1</bitWidth>
            </field>
            <field>
              <name>PLLI2SRDYF</name>
              <bitOffset>5</bitOffset>
              <bitWidth>1</bitWidth>
            </field>
            <field>
              <name>CSSF</name>
              <bitOffset>7</bitOffset>
              <bitWidth>1</bitWidth>
            </field>
            <field>
              <name>LSIRDYIE</name>
              <bitOffset>8</bitOffset>
              <bitWidth>1</bitWidth>
            </field>
            <field>
              <name>LSERDYIE</name>
              <bitOffset>9</bitOffset>
              <bitWidth>1</bitWidth>
            </field>
            <field>
              <name>HSIRDYIE</name>
              <bitOffset>10</bitOffset>
              <bitWidth>1</bitWidth>
            </field>
            <field>
              <name>HSERDYIE</name>
              <bitOffset>11</bitOffset>
              <bitWidth>1</bitWidth>
            </field>
            <field>
              <name>PLLRDYIE</name>
              <bitOffset>12</bitOffset>
              <bitWidth>1</bitWidth>
            </field>
            <field>
              <name>PLLI2SRDYIE</name>
              <bitOffset>13</bitOffset>
              <bitWidth>1</bitWidth>
            </field>
            <field>
              <name>LSIRDYC</name>
              <bitOffset>16</bitOffset>
              <bitWidth>1</bitWidth>
            </field>
            <field>
              <name>LSERDYC</name>
              <bitOffset>17</bitOffset>
              <bitWidth>1</bitWidth>
            </field>
            <field>
              <name>HSIRDYC</name>
              <bitOffset>18</bitOffset>
              <bitWidth>1</bitWidth>
            </field>
            <field>
              <name>HSERDYC</name>
              <bitOffset>19</bitOffset>
              <bitWidth>1</bitWidth>
            </field>
            <field>
              <name>PLLRDYC</name>
              <bitOffset>20</bitOffset>
              <bitWidth>1</bitWidth>
            </field>
            <field>
              <name>PLLI2SRDYC</name>
              <bitOffset>21</bitOffset>
              <bitWidth>1</bitWidth>
            </field>
            <field>
              <name>CSSC</name>
              <bitOffset>23</bitOffset>
              <bitWidth>1</bitWidth>
            </field>
          </fields>
        </register>
        <register>
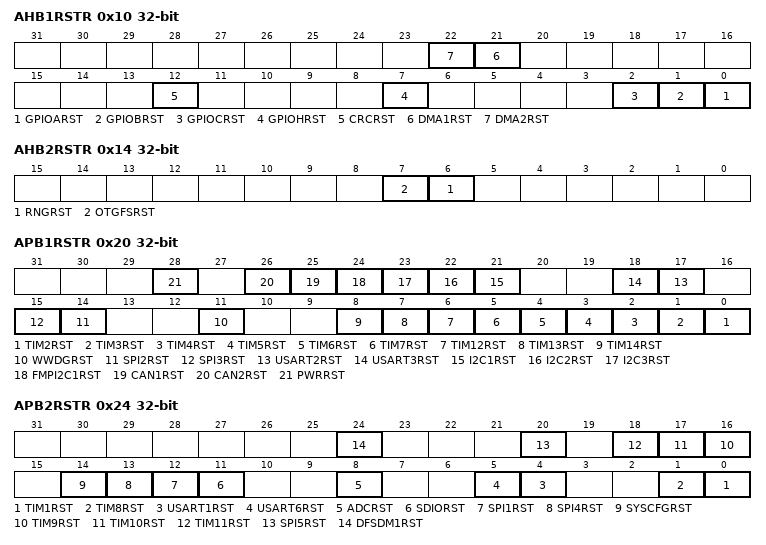
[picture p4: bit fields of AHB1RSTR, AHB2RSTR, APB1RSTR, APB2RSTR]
          <name>AHB1RSTR</name>
          <addressOffset>0x10</addressOffset>
          <size>0x20</size>
          <fields>
            <field>
              <name>GPIOARST</name>
              <bitOffset>0</bitOffset>
              <bitWidth>1</bitWidth>
            </field>
            <field>
              <name>GPIOBRST</name>
              <bitOffset>1</bitOffset>
              <bitWidth>1</bitWidth>
            </field>
            <field>
              <name>GPIOCRST</name>
              <bitOffset>2</bitOffset>
              <bitWidth>1</bitWidth>
            </field>
            <field>
              <name>GPIOHRST</name>
              <bitOffset>7</bitOffset>
              <bitWidth>1</bitWidth>
            </field>
            <field>
              <name>CRCRST</name>
              <bitOffset>12</bitOffset>
              <bitWidth>1</bitWidth>
            </field>
            <field>
              <name>DMA1RST</name>
              <bitOffset>21</bitOffset>
              <bitWidth>1</bitWidth>
            </field>
            <field>
              <name>DMA2RST</name>
              <bitOffset>22</bitOffset>
              <bitWidth>1</bitWidth>
            </field>
          </fields>
        </register>
        <register>
          <name>AHB2RSTR</name>
          <addressOffset>0x14</addressOffset>
          <size>0x20</size>
          <fields>
            <field>
              <name>RNGRST</name>
              <bitOffset>6</bitOffset>
              <bitWidth>1</bitWidth>
            </field>
            <field>
              <name>OTGFSRST</name>
              <bitOffset>7</bitOffset>
              <bitWidth>1</bitWidth>
            </field>
          </fields>
        </register>
        <register>
          <name>APB1RSTR</name>
          <addressOffset>0x20</addressOffset>
          <size>0x20</size>
          <fields>
            <field>
              <name>TIM2RST</name>
              <bitOffset>0</bitOffset>
              <bitWidth>1</bitWidth>
            </field>
            <field>
              <name>TIM3RST</name>
              <bitOffset>1</bitOffset>
              <bitWidth>1</bitWidth>
            </field>
            <field>
              <name>TIM4RST</name>
              <bitOffset>2</bitOffset>
              <bitWidth>1</bitWidth>
            </field>
            <field>
              <name>TIM5RST</name>
              <bitOffset>3</bitOffset>
              <bitWidth>1</bitWidth>
            </field>
            <field>
              <name>TIM6RST</name>
              <bitOffset>4</bitOffset>
              <bitWidth>1</bitWidth>
            </field>
            <field>
              <name>TIM7RST</name>
              <bitOffset>5</bitOffset>
              <bitWidth>1</bitWidth>
            </field>
            <field>
              <name>TIM12RST</name>
              <bitOffset>6</bitOffset>
              <bitWidth>1</bitWidth>
            </field>
            <field>
              <name>TIM13RST</name>
              <bitOffset>7</bitOffset>
              <bitWidth>1</bitWidth>
            </field>
            <field>
              <name>TIM14RST</name>
              <bitOffset>8</bitOffset>
              <bitWidth>1</bitWidth>
            </field>
            <field>
              <name>WWDGRST</name>
              <bitOffset>11</bitOffset>
              <bitWidth>1</bitWidth>
            </field>
            <field>
              <name>SPI2RST</name>
              <bitOffset>14</bitOffset>
              <bitWidth>1</bitWidth>
            </field>
            <field>
              <name>SPI3RST</name>
              <bitOffset>15</bitOffset>
              <bitWidth>1</bitWidth>
            </field>
            <field>
              <name>USART2RST</name>
              <bitOffset>17</bitOffset>
              <bitWidth>1</bitWidth>
            </field>
            <field>
              <name>USART3RST</name>
              <bitOffset>18</bitOffset>
              <bitWidth>1</bitWidth>
            </field>
            <field>
              <name>I2C1RST</name>
              <bitOffset>21</bitOffset>
              <bitWidth>1</bitWidth>
            </field>
            <field>
              <name>I2C2RST</name>
              <bitOffset>22</bitOffset>
              <bitWidth>1</bitWidth>
            </field>
            <field>
              <name>I2C3RST</name>
              <bitOffset>23</bitOffset>
              <bitWidth>1</bitWidth>
            </field>
            <field>
              <name>FMPI2C1RST</name>
              <bitOffset>24</bitOffset>
              <bitWidth>1</bitWidth>
            </field>
            <field>
              <name>CAN1RST</name>
              <bitOffset>25</bitOffset>
              <bitWidth>1</bitWidth>
            </field>
            <field>
              <name>CAN2RST</name>
              <bitOffset>26</bitOffset>
              <bitWidth>1</bitWidth>
            </field>
            <field>
              <name>PWRRST</name>
              <bitOffset>28</bitOffset>
              <bitWidth>1</bitWidth>
            </field>
          </fields>
        </register>
        <register>
          <name>APB2RSTR</name>
          <addressOffset>0x24</addressOffset>
          <size>0x20</size>
          <fields>
            <field>
              <name>TIM1RST</name>
              <bitOffset>0</bitOffset>
              <bitWidth>1</bitWidth>
            </field>
            <field>
              <name>TIM8RST</name>
              <bitOffset>1</bitOffset>
              <bitWidth>1</bitWidth>
            </field>
            <field>
              <name>USART1RST</name>
              <bitOffset>4</bitOffset>
              <bitWidth>1</bitWidth>
            </field>
            <field>
              <name>USART6RST</name>
              <bitOffset>5</bitOffset>
              <bitWidth>1</bitWidth>
            </field>
            <field>
              <name>ADCRST</name>
              <bitOffset>8</bitOffset>
              <bitWidth>1</bitWidth>
            </field>
            <field>
              <name>SDIORST</name>
              <bitOffset>11</bitOffset>
              <bitWidth>1</bitWidth>
            </field>
            <field>
              <name>SPI1RST</name>
              <bitOffset>12</bitOffset>
              <bitWidth>1</bitWidth>
            </field>
            <field>
              <name>SPI4RST</name>
              <bitOffset>13</bitOffset>
              <bitWidth>1</bitWidth>
            </field>
            <field>
              <name>SYSCFGRST</name>
              <bitOffset>14</bitOffset>
              <bitWidth>1</bitWidth>
            </field>
            <field>
              <name>TIM9RST</name>
              <bitOffset>16</bitOffset>
              <bitWidth>1</bitWidth>
            </field>
            <field>
              <name>TIM10RST</name>
              <bitOffset>17</bitOffset>
              <bitWidth>1</bitWidth>
            </field>
            <field>
              <name>TIM11RST</name>
              <bitOffset>18</bitOffset>
              <bitWidth>1</bitWidth>
            </field>
            <field>
              <name>SPI5RST</name>
              <bitOffset>20</bitOffset>
              <bitWidth>1</bitWidth>
            </field>
            <field>
              <name>DFSDM1RST</name>
              <bitOffset>24</bitOffset>
              <bitWidth>1</bitWidth>
            </field>
          </fields>
        </register>
        <register>
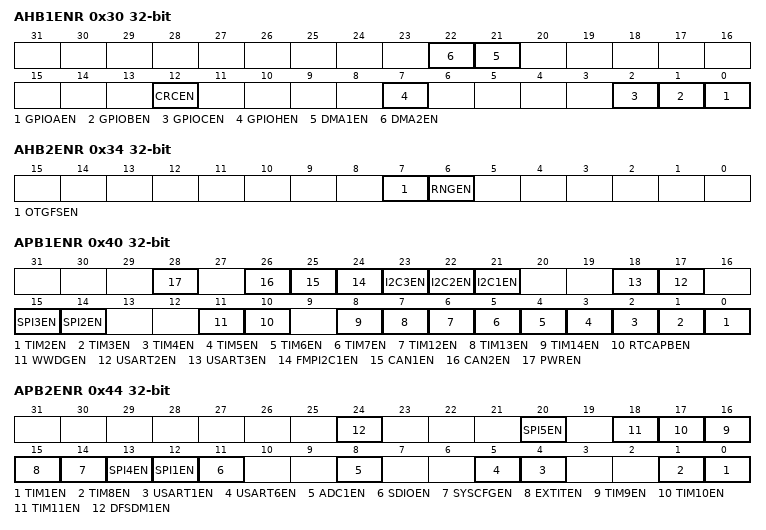
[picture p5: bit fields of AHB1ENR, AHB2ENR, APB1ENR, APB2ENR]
          <name>AHB1ENR</name>
          <addressOffset>0x30</addressOffset>
          <size>0x20</size>
          <fields>
            <field>
              <name>GPIOAEN</name>
              <bitOffset>0</bitOffset>
              <bitWidth>1</bitWidth>
            </field>
            <field>
              <name>GPIOBEN</name>
              <bitOffset>1</bitOffset>
              <bitWidth>1</bitWidth>
            </field>
            <field>
              <name>GPIOCEN</name>
              <bitOffset>2</bitOffset>
              <bitWidth>1</bitWidth>
            </field>
            <field>
              <name>GPIOHEN</name>
              <bitOffset>7</bitOffset>
              <bitWidth>1</bitWidth>
            </field>
            <field>
              <name>CRCEN</name>
              <bitOffset>12</bitOffset>
              <bitWidth>1</bitWidth>
            </field>
            <field>
              <name>DMA1EN</name>
              <bitOffset>21</bitOffset>
              <bitWidth>1</bitWidth>
            </field>
            <field>
              <name>DMA2EN</name>
              <bitOffset>22</bitOffset>
              <bitWidth>1</bitWidth>
            </field>
          </fields>
        </register>
        <register>
          <name>AHB2ENR</name>
          <addressOffset>0x34</addressOffset>
          <size>0x20</size>
          <fields>
            <field>
              <name>RNGEN</name>
              <bitOffset>6</bitOffset>
              <bitWidth>1</bitWidth>
            </field>
            <field>
              <name>OTGFSEN</name>
              <bitOffset>7</bitOffset>
              <bitWidth>1</bitWidth>
            </field>
          </fields>
        </register>
        <register>
          <name>APB1ENR</name>
          <addressOffset>0x40</addressOffset>
          <size>0x20</size>
          <fields>
            <field>
              <name>TIM2EN</name>
              <bitOffset>0</bitOffset>
              <bitWidth>1</bitWidth>
            </field>
            <field>
              <name>TIM3EN</name>
              <bitOffset>1</bitOffset>
              <bitWidth>1</bitWidth>
            </field>
            <field>
              <name>TIM4EN</name>
              <bitOffset>2</bitOffset>
              <bitWidth>1</bitWidth>
            </field>
            <field>
              <name>TIM5EN</name>
              <bitOffset>3</bitOffset>
              <bitWidth>1</bitWidth>
            </field>
            <field>
              <name>TIM6EN</name>
              <bitOffset>4</bitOffset>
              <bitWidth>1</bitWidth>
            </field>
            <field>
              <name>TIM7EN</name>
              <bitOffset>5</bitOffset>
              <bitWidth>1</bitWidth>
            </field>
            <field>
              <name>TIM12EN</name>
              <bitOffset>6</bitOffset>
              <bitWidth>1</bitWidth>
            </field>
            <field>
              <name>TIM13EN</name>
              <bitOffset>7</bitOffset>
              <bitWidth>1</bitWidth>
            </field>
            <field>
              <name>TIM14EN</name>
              <bitOffset>8</bitOffset>
              <bitWidth>1</bitWidth>
            </field>
            <field>
              <name>RTCAPBEN</name>
              <bitOffset>10</bitOffset>
              <bitWidth>1</bitWidth>
            </field>
            <field>
              <name>WWDGEN</name>
              <bitOffset>11</bitOffset>
              <bitWidth>1</bitWidth>
            </field>
            <field>
              <name>SPI2EN</name>
              <bitOffset>14</bitOffset>
              <bitWidth>1</bitWidth>
            </field>
            <field>
              <name>SPI3EN</name>
              <bitOffset>15</bitOffset>
              <bitWidth>1</bitWidth>
            </field>
            <field>
              <name>USART2EN</name>
              <bitOffset>17</bitOffset>
              <bitWidth>1</bitWidth>
            </field>
            <field>
              <name>USART3EN</name>
              <bitOffset>18</bitOffset>
              <bitWidth>1</bitWidth>
            </field>
            <field>
              <name>I2C1EN</name>
              <bitOffset>21</bitOffset>
              <bitWidth>1</bitWidth>
            </field>
            <field>
              <name>I2C2EN</name>
              <bitOffset>22</bitOffset>
              <bitWidth>1</bitWidth>
            </field>
            <field>
              <name>I2C3EN</name>
              <bitOffset>23</bitOffset>
              <bitWidth>1</bitWidth>
            </field>
            <field>
              <name>FMPI2C1EN</name>
              <bitOffset>24</bitOffset>
              <bitWidth>1</bitWidth>
            </field>
            <field>
              <name>CAN1EN</name>
              <bitOffset>25</bitOffset>
              <bitWidth>1</bitWidth>
            </field>
            <field>
              <name>CAN2EN</name>
              <bitOffset>26</bitOffset>
              <bitWidth>1</bitWidth>
            </field>
            <field>
              <name>PWREN</name>
              <bitOffset>28</bitOffset>
              <bitWidth>1</bitWidth>
            </field>
          </fields>
        </register>
        <register>
          <name>APB2ENR</name>
          <addressOffset>0x44</addressOffset>
          <size>0x20</size>
          <fields>
            <field>
              <name>TIM1EN</name>
              <bitOffset>0</bitOffset>
              <bitWidth>1</bitWidth>
            </field>
            <field>
              <name>TIM8EN</name>
              <bitOffset>1</bitOffset>
              <bitWidth>1</bitWidth>
            </field>
            <field>
              <name>USART1EN</name>
              <bitOffset>4</bitOffset>
              <bitWidth>1</bitWidth>
            </field>
            <field>
              <name>USART6EN</name>
              <bitOffset>5</bitOffset>
              <bitWidth>1</bitWidth>
            </field>
            <field>
              <name>ADC1EN</name>
              <bitOffset>8</bitOffset>
              <bitWidth>1</bitWidth>
            </field>
            <field>
              <name>SDIOEN</name>
              <bitOffset>11</bitOffset>
              <bitWidth>1</bitWidth>
            </field>
            <field>
              <name>SPI1EN</name>
              <bitOffset>12</bitOffset>
              <bitWidth>1</bitWidth>
            </field>
            <field>
              <name>SPI4EN</name>
              <bitOffset>13</bitOffset>
              <bitWidth>1</bitWidth>
            </field>
            <field>
              <name>SYSCFGEN</name>
              <bitOffset>14</bitOffset>
              <bitWidth>1</bitWidth>
            </field>
            <field>
              <name>EXTITEN</name>
              <bitOffset>15</bitOffset>
              <bitWidth>1</bitWidth>
            </field>
            <field>
              <name>TIM9EN</name>
              <bitOffset>16</bitOffset>
              <bitWidth>1</bitWidth>
            </field>
            <field>
              <name>TIM10EN</name>
              <bitOffset>17</bitOffset>
              <bitWidth>1</bitWidth>
            </field>
            <field>
              <name>TIM11EN</name>
              <bitOffset>18</bitOffset>
              <bitWidth>1</bitWidth>
            </field>
            <field>
              <name>SPI5EN</name>
              <bitOffset>20</bitOffset>
              <bitWidth>1</bitWidth>
            </field>
            <field>
              <name>DFSDM1EN</name>
              <bitOffset>24</bitOffset>
              <bitWidth>1</bitWidth>
            </field>
          </fields>
        </register>
        <register>
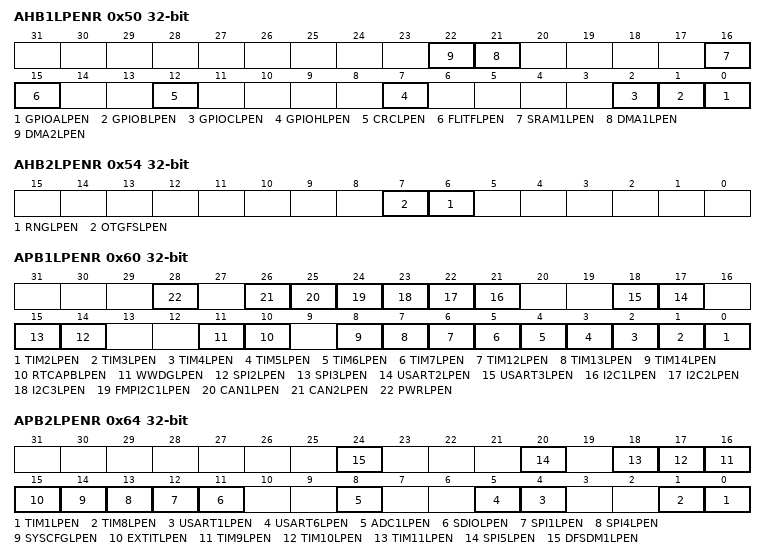
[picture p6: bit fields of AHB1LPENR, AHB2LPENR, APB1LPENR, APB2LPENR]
          <name>AHB1LPENR</name>
          <addressOffset>0x50</addressOffset>
          <size>0x20</size>
          <fields>
            <field>
              <name>GPIOALPEN</name>
              <bitOffset>0</bitOffset>
              <bitWidth>1</bitWidth>
            </field>
            <field>
              <name>GPIOBLPEN</name>
              <bitOffset>1</bitOffset>
              <bitWidth>1</bitWidth>
            </field>
            <field>
              <name>GPIOCLPEN</name>
              <bitOffset>2</bitOffset>
              <bitWidth>1</bitWidth>
            </field>
            <field>
              <name>GPIOHLPEN</name>
              <bitOffset>7</bitOffset>
              <bitWidth>1</bitWidth>
            </field>
            <field>
              <name>CRCLPEN</name>
              <bitOffset>12</bitOffset>
              <bitWidth>1</bitWidth>
            </field>
            <field>
              <name>FLITFLPEN</name>
              <bitOffset>15</bitOffset>
              <bitWidth>1</bitWidth>
            </field>
            <field>
              <name>SRAM1LPEN</name>
              <bitOffset>16</bitOffset>
              <bitWidth>1</bitWidth>
            </field>
            <field>
              <name>DMA1LPEN</name>
              <bitOffset>21</bitOffset>
              <bitWidth>1</bitWidth>
            </field>
            <field>
              <name>DMA2LPEN</name>
              <bitOffset>22</bitOffset>
              <bitWidth>1</bitWidth>
            </field>
          </fields>
        </register>
        <register>
          <name>AHB2LPENR</name>
          <addressOffset>0x54</addressOffset>
          <size>0x20</size>
          <fields>
            <field>
              <name>RNGLPEN</name>
              <bitOffset>6</bitOffset>
              <bitWidth>1</bitWidth>
            </field>
            <field>
              <name>OTGFSLPEN</name>
              <bitOffset>7</bitOffset>
              <bitWidth>1</bitWidth>
            </field>
          </fields>
        </register>
        <register>
          <name>APB1LPENR</name>
          <addressOffset>0x60</addressOffset>
          <size>0x20</size>
          <fields>
            <field>
              <name>TIM2LPEN</name>
              <bitOffset>0</bitOffset>
              <bitWidth>1</bitWidth>
            </field>
            <field>
              <name>TIM3LPEN</name>
              <bitOffset>1</bitOffset>
              <bitWidth>1</bitWidth>
            </field>
            <field>
              <name>TIM4LPEN</name>
              <bitOffset>2</bitOffset>
              <bitWidth>1</bitWidth>
            </field>
            <field>
              <name>TIM5LPEN</name>
              <bitOffset>3</bitOffset>
              <bitWidth>1</bitWidth>
            </field>
            <field>
              <name>TIM6LPEN</name>
              <bitOffset>4</bitOffset>
              <bitWidth>1</bitWidth>
            </field>
            <field>
              <name>TIM7LPEN</name>
              <bitOffset>5</bitOffset>
              <bitWidth>1</bitWidth>
            </field>
            <field>
              <name>TIM12LPEN</name>
              <bitOffset>6</bitOffset>
              <bitWidth>1</bitWidth>
            </field>
            <field>
              <name>TIM13LPEN</name>
              <bitOffset>7</bitOffset>
              <bitWidth>1</bitWidth>
            </field>
            <field>
              <name>TIM14LPEN</name>
              <bitOffset>8</bitOffset>
              <bitWidth>1</bitWidth>
            </field>
            <field>
              <name>RTCAPBLPEN</name>
              <bitOffset>10</bitOffset>
              <bitWidth>1</bitWidth>
            </field>
            <field>
              <name>WWDGLPEN</name>
              <bitOffset>11</bitOffset>
              <bitWidth>1</bitWidth>
            </field>
            <field>
              <name>SPI2LPEN</name>
              <bitOffset>14</bitOffset>
              <bitWidth>1</bitWidth>
            </field>
            <field>
              <name>SPI3LPEN</name>
              <bitOffset>15</bitOffset>
              <bitWidth>1</bitWidth>
            </field>
            <field>
              <name>USART2LPEN</name>
              <bitOffset>17</bitOffset>
              <bitWidth>1</bitWidth>
            </field>
            <field>
              <name>USART3LPEN</name>
              <bitOffset>18</bitOffset>
              <bitWidth>1</bitWidth>
            </field>
            <field>
              <name>I2C1LPEN</name>
              <bitOffset>21</bitOffset>
              <bitWidth>1</bitWidth>
            </field>
            <field>
              <name>I2C2LPEN</name>
              <bitOffset>22</bitOffset>
              <bitWidth>1</bitWidth>
            </field>
            <field>
              <name>I2C3LPEN</name>
              <bitOffset>23</bitOffset>
              <bitWidth>1</bitWidth>
            </field>
            <field>
              <name>FMPI2C1LPEN</name>
              <bitOffset>24</bitOffset>
              <bitWidth>1</bitWidth>
            </field>
            <field>
              <name>CAN1LPEN</name>
              <bitOffset>25</bitOffset>
              <bitWidth>1</bitWidth>
            </field>
            <field>
              <name>CAN2LPEN</name>
              <bitOffset>26</bitOffset>
              <bitWidth>1</bitWidth>
            </field>
            <field>
              <name>PWRLPEN</name>
              <bitOffset>28</bitOffset>
              <bitWidth>1</bitWidth>
            </field>
          </fields>
        </register>
        <register>
          <name>APB2LPENR</name>
          <addressOffset>0x64</addressOffset>
          <size>0x20</size>
          <fields>
            <field>
              <name>TIM1LPEN</name>
              <bitOffset>0</bitOffset>
              <bitWidth>1</bitWidth>
            </field>
            <field>
              <name>TIM8LPEN</name>
              <bitOffset>1</bitOffset>
              <bitWidth>1</bitWidth>
            </field>
            <field>
              <name>USART1LPEN</name>
              <bitOffset>4</bitOffset>
              <bitWidth>1</bitWidth>
            </field>
            <field>
              <name>USART6LPEN</name>
              <bitOffset>5</bitOffset>
              <bitWidth>1</bitWidth>
            </field>
            <field>
              <name>ADC1LPEN</name>
              <bitOffset>8</bitOffset>
              <bitWidth>1</bitWidth>
            </field>
            <field>
              <name>SDIOLPEN</name>
              <bitOffset>11</bitOffset>
              <bitWidth>1</bitWidth>
            </field>
            <field>
              <name>SPI1LPEN</name>
              <bitOffset>12</bitOffset>
              <bitWidth>1</bitWidth>
            </field>
            <field>
              <name>SPI4LPEN</name>
              <bitOffset>13</bitOffset>
              <bitWidth>1</bitWidth>
            </field>
            <field>
              <name>SYSCFGLPEN</name>
              <bitOffset>14</bitOffset>
              <bitWidth>1</bitWidth>
            </field>
            <field>
              <name>EXTITLPEN</name>
              <bitOffset>15</bitOffset>
              <bitWidth>1</bitWidth>
            </field>
            <field>
              <name>TIM9LPEN</name>
              <bitOffset>16</bitOffset>
              <bitWidth>1</bitWidth>
            </field>
            <field>
              <name>TIM10LPEN</name>
              <bitOffset>17</bitOffset>
              <bitWidth>1</bitWidth>
            </field>
            <field>
              <name>TIM11LPEN</name>
              <bitOffset>18</bitOffset>
              <bitWidth>1</bitWidth>
            </field>
            <field>
              <name>SPI5LPEN</name>
              <bitOffset>20</bitOffset>
              <bitWidth>1</bitWidth>
            </field>
            <field>
              <name>DFSDM1LPEN</name>
              <bitOffset>24</bitOffset>
              <bitWidth>1</bitWidth>
            </field>
          </fields>
        </register>
        <register>
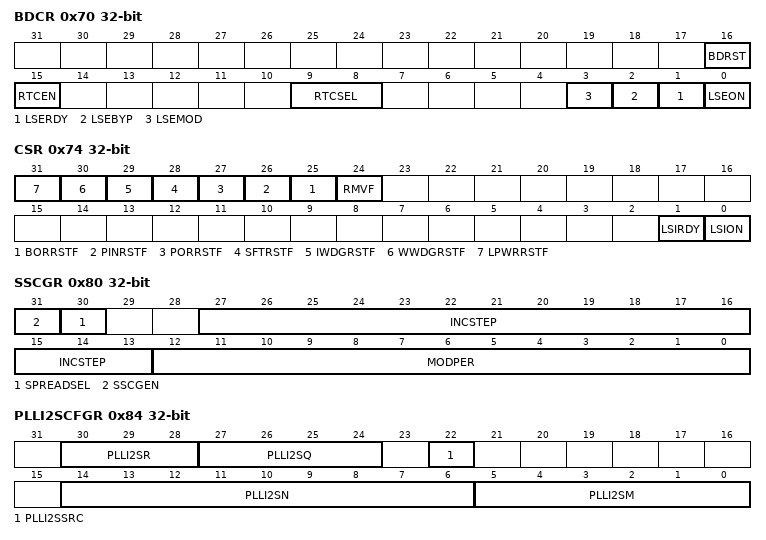
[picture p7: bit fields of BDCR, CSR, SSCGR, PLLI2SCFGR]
          <name>BDCR</name>
          <addressOffset>0x70</addressOffset>
          <size>0x20</size>
          <fields>
            <field>
              <name>LSEON</name>
              <bitOffset>0</bitOffset>
              <bitWidth>1</bitWidth>
            </field>
            <field>
              <name>LSERDY</name>
              <bitOffset>1</bitOffset>
              <bitWidth>1</bitWidth>
            </field>
            <field>
              <name>LSEBYP</name>
              <bitOffset>2</bitOffset>
              <bitWidth>1</bitWidth>
            </field>
            <field>
              <name>LSEMOD</name>
              <bitOffset>3</bitOffset>
              <bitWidth>1</bitWidth>
            </field>
            <field>
              <name>RTCSEL</name>
              <bitOffset>8</bitOffset>
              <bitWidth>2</bitWidth>
            </field>
            <field>
              <name>RTCEN</name>
              <bitOffset>15</bitOffset>
              <bitWidth>1</bitWidth>
            </field>
            <field>
              <name>BDRST</name>
              <bitOffset>16</bitOffset>
              <bitWidth>1</bitWidth>
            </field>
          </fields>
        </register>
        <register>
          <name>CSR</name>
          <addressOffset>0x74</addressOffset>
          <size>0x20</size>
          <fields>
            <field>
              <name>LSION</name>
              <bitOffset>0</bitOffset>
              <bitWidth>1</bitWidth>
            </field>
            <field>
              <name>LSIRDY</name>
              <bitOffset>1</bitOffset>
              <bitWidth>1</bitWidth>
            </field>
            <field>
              <name>RMVF</name>
              <bitOffset>24</bitOffset>
              <bitWidth>1</bitWidth>
            </field>
            <field>
              <name>BORRSTF</name>
              <bitOffset>25</bitOffset>
              <bitWidth>1</bitWidth>
            </field>
            <field>
              <name>PINRSTF</name>
              <bitOffset>26</bitOffset>
              <bitWidth>1</bitWidth>
            </field>
            <field>
              <name>PORRSTF</name>
              <bitOffset>27</bitOffset>
              <bitWidth>1</bitWidth>
            </field>
            <field>
              <name>SFTRSTF</name>
              <bitOffset>28</bitOffset>
              <bitWidth>1</bitWidth>
            </field>
            <field>
              <name>IWDGRSTF</name>
              <bitOffset>29</bitOffset>
              <bitWidth>1</bitWidth>
            </field>
            <field>
              <name>WWDGRSTF</name>
              <bitOffset>30</bitOffset>
              <bitWidth>1</bitWidth>
            </field>
            <field>
              <name>LPWRRSTF</name>
              <bitOffset>31</bitOffset>
              <bitWidth>1</bitWidth>
            </field>
          </fields>
        </register>
        <register>
          <name>SSCGR</name>
          <addressOffset>0x80</addressOffset>
          <size>0x20</size>
          <fields>
            <field>
              <name>MODPER</name>
              <bitOffset>0</bitOffset>
              <bitWidth>13</bitWidth>
            </field>
            <field>
              <name>INCSTEP</name>
              <bitOffset>13</bitOffset>
              <bitWidth>15</bitWidth>
            </field>
            <field>
              <name>SPREADSEL</name>
              <bitOffset>30</bitOffset>
              <bitWidth>1</bitWidth>
            </field>
            <field>
              <name>SSCGEN</name>
              <bitOffset>31</bitOffset>
              <bitWidth>1</bitWidth>
            </field>
          </fields>
        </register>
        <register>
          <name>PLLI2SCFGR</name>
          <addressOffset>0x84</addressOffset>
          <size>0x20</size>
          <fields>
            <field>
              <name>PLLI2SM</name>
              <bitOffset>0</bitOffset>
              <bitWidth>6</bitWidth>
            </field>
            <field>
              <name>PLLI2SN</name>
              <bitOffset>6</bitOffset>
              <bitWidth>9</bitWidth>
            </field>
            <field>
              <name>PLLI2SSRC</name>
              <bitOffset>22</bitOffset>
              <bitWidth>1</bitWidth>
            </field>
            <field>
              <name>PLLI2SQ</name>
              <bitOffset>24</bitOffset>
              <bitWidth>4</bitWidth>
            </field>
            <field>
              <name>PLLI2SR</name>
              <bitOffset>28</bitOffset>
              <bitWidth>3</bitWidth>
            </field>
          </fields>
        </register>
        <register>
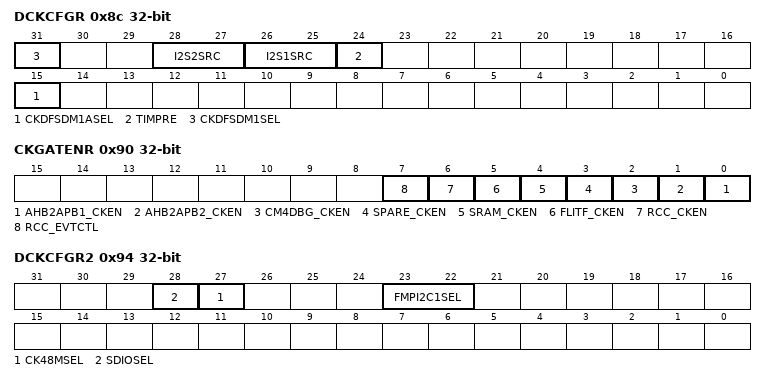
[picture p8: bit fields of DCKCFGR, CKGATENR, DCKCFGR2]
          <name>DCKCFGR</name>
          <addressOffset>0x8c</addressOffset>
          <size>0x20</size>
          <fields>
            <field>
              <name>CKDFSDM1ASEL</name>
              <bitOffset>15</bitOffset>
              <bitWidth>1</bitWidth>
            </field>
            <field>
              <name>TIMPRE</name>
              <bitOffset>24</bitOffset>
              <bitWidth>1</bitWidth>
            </field>
            <field>
              <name>I2S1SRC</name>
              <bitOffset>25</bitOffset>
              <bitWidth>2</bitWidth>
            </field>
            <field>
              <name>I2S2SRC</name>
              <bitOffset>27</bitOffset>
              <bitWidth>2</bitWidth>
            </field>
            <field>
              <name>CKDFSDM1SEL</name>
              <bitOffset>31</bitOffset>
              <bitWidth>1</bitWidth>
            </field>
          </fields>
        </register>
        <register>
          <name>CKGATENR</name>
          <addressOffset>0x90</addressOffset>
          <size>0x20</size>
          <fields>
            <field>
              <name>AHB2APB1_CKEN</name>
              <bitOffset>0</bitOffset>
              <bitWidth>1</bitWidth>
            </field>
            <field>
              <name>AHB2APB2_CKEN</name>
              <bitOffset>1</bitOffset>
              <bitWidth>1</bitWidth>
            </field>
            <field>
              <name>CM4DBG_CKEN</name>
              <bitOffset>2</bitOffset>
              <bitWidth>1</bitWidth>
            </field>
            <field>
              <name>SPARE_CKEN</name>
              <bitOffset>3</bitOffset>
              <bitWidth>1</bitWidth>
            </field>
            <field>
              <name>SRAM_CKEN</name>
              <bitOffset>4</bitOffset>
              <bitWidth>1</bitWidth>
            </field>
            <field>
              <name>FLITF_CKEN</name>
              <bitOffset>5</bitOffset>
              <bitWidth>1</bitWidth>
            </field>
            <field>
              <name>RCC_CKEN</name>
              <bitOffset>6</bitOffset>
              <bitWidth>1</bitWidth>
            </field>
            <field>
              <name>RCC_EVTCTL</name>
              <bitOffset>7</bitOffset>
              <bitWidth>1</bitWidth>
            </field>
          </fields>
        </register>
        <register>
          <name>DCKCFGR2</name>
          <addressOffset>0x94</addressOffset>
          <size>0x20</size>
          <fields>
            <field>
              <name>FMPI2C1SEL</name>
              <bitOffset>22</bitOffset>
              <bitWidth>2</bitWidth>
            </field>
            <field>
              <name>CK48MSEL</name>
              <bitOffset>27</bitOffset>
              <bitWidth>1</bitWidth>
            </field>
            <field>
              <name>SDIOSEL</name>
              <bitOffset>28</bitOffset>
              <bitWidth>1</bitWidth>
            </field>
          </fields>
        </register>
      </registers>
    </peripheral>
    <peripheral>
      <name>FLASH</name>
      <baseAddress>0x40023c00</baseAddress>
      <registers>
        <register>
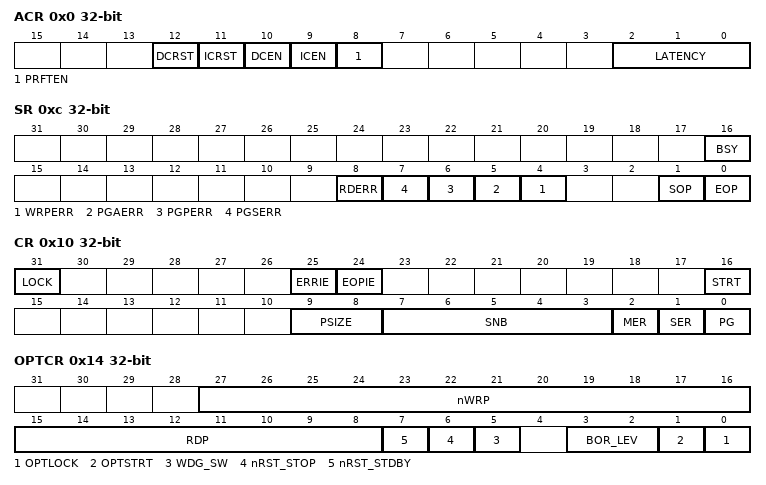
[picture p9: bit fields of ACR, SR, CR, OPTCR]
          <name>ACR</name>
          <addressOffset>0x0</addressOffset>
          <size>0x20</size>
          <fields>
            <field>
              <name>LATENCY</name>
              <bitOffset>0</bitOffset>
              <bitWidth>3</bitWidth>
            </field>
            <field>
              <name>PRFTEN</name>
              <bitOffset>8</bitOffset>
              <bitWidth>1</bitWidth>
            </field>
            <field>
              <name>ICEN</name>
              <bitOffset>9</bitOffset>
              <bitWidth>1</bitWidth>
            </field>
            <field>
              <name>DCEN</name>
              <bitOffset>10</bitOffset>
              <bitWidth>1</bitWidth>
            </field>
            <field>
              <name>ICRST</name>
              <bitOffset>11</bitOffset>
              <bitWidth>1</bitWidth>
            </field>
            <field>
              <name>DCRST</name>
              <bitOffset>12</bitOffset>
              <bitWidth>1</bitWidth>
            </field>
          </fields>
        </register>
        <register>
          <name>KEYR</name>
          <addressOffset>0x4</addressOffset>
          <size>0x20</size>
        </register>
        <register>
          <name>OPTKEYR</name>
          <addressOffset>0x8</addressOffset>
          <size>0x20</size>
        </register>
        <register>
          <name>SR</name>
          <addressOffset>0xc</addressOffset>
          <size>0x20</size>
          <fields>
            <field>
              <name>EOP</name>
              <bitOffset>0</bitOffset>
              <bitWidth>1</bitWidth>
            </field>
            <field>
              <name>SOP</name>
              <bitOffset>1</bitOffset>
              <bitWidth>1</bitWidth>
            </field>
            <field>
              <name>WRPERR</name>
              <bitOffset>4</bitOffset>
              <bitWidth>1</bitWidth>
            </field>
            <field>
              <name>PGAERR</name>
              <bitOffset>5</bitOffset>
              <bitWidth>1</bitWidth>
            </field>
            <field>
              <name>PGPERR</name>
              <bitOffset>6</bitOffset>
              <bitWidth>1</bitWidth>
            </field>
            <field>
              <name>PGSERR</name>
              <bitOffset>7</bitOffset>
              <bitWidth>1</bitWidth>
            </field>
            <field>
              <name>RDERR</name>
              <bitOffset>8</bitOffset>
              <bitWidth>1</bitWidth>
            </field>
            <field>
              <name>BSY</name>
              <bitOffset>16</bitOffset>
              <bitWidth>1</bitWidth>
            </field>
          </fields>
        </register>
        <register>
          <name>CR</name>
          <addressOffset>0x10</addressOffset>
          <size>0x20</size>
          <fields>
            <field>
              <name>PG</name>
              <bitOffset>0</bitOffset>
              <bitWidth>1</bitWidth>
            </field>
            <field>
              <name>SER</name>
              <bitOffset>1</bitOffset>
              <bitWidth>1</bitWidth>
            </field>
            <field>
              <name>MER</name>
              <bitOffset>2</bitOffset>
              <bitWidth>1</bitWidth>
            </field>
            <field>
              <name>SNB</name>
              <bitOffset>3</bitOffset>
              <bitWidth>5</bitWidth>
            </field>
            <field>
              <name>PSIZE</name>
              <bitOffset>8</bitOffset>
              <bitWidth>2</bitWidth>
            </field>
            <field>
              <name>STRT</name>
              <bitOffset>16</bitOffset>
              <bitWidth>1</bitWidth>
            </field>
            <field>
              <name>EOPIE</name>
              <bitOffset>24</bitOffset>
              <bitWidth>1</bitWidth>
            </field>
            <field>
              <name>ERRIE</name>
              <bitOffset>25</bitOffset>
              <bitWidth>1</bitWidth>
            </field>
            <field>
              <name>LOCK</name>
              <bitOffset>31</bitOffset>
              <bitWidth>1</bitWidth>
            </field>
          </fields>
        </register>
        <register>
          <name>OPTCR</name>
          <addressOffset>0x14</addressOffset>
          <size>0x20</size>
          <fields>
            <field>
              <name>OPTLOCK</name>
              <bitOffset>0</bitOffset>
              <bitWidth>1</bitWidth>
            </field>
            <field>
              <name>OPTSTRT</name>
              <bitOffset>1</bitOffset>
              <bitWidth>1</bitWidth>
            </field>
            <field>
              <name>BOR_LEV</name>
              <bitOffset>2</bitOffset>
              <bitWidth>2</bitWidth>
            </field>
            <field>
              <name>WDG_SW</name>
              <bitOffset>5</bitOffset>
              <bitWidth>1</bitWidth>
            </field>
            <field>
              <name>nRST_STOP</name>
              <bitOffset>6</bitOffset>
              <bitWidth>1</bitWidth>
            </field>
            <field>
              <name>nRST_STDBY</name>
              <bitOffset>7</bitOffset>
              <bitWidth>1</bitWidth>
            </field>
            <field>
              <name>RDP</name>
              <bitOffset>8</bitOffset>
              <bitWidth>8</bitWidth>
            </field>
            <field>
              <name>nWRP</name>
              <bitOffset>16</bitOffset>
              <bitWidth>12</bitWidth>
            </field>
          </fields>
        </register>
        <register>
          <name>OPTCR1</name>
          <addressOffset>0x18</addressOffset>
          <size>0x20</size>
          <fields>
            <field>
              <name>nWRP</name>
              <bitOffset>16</bitOffset>
              <bitWidth>12</bitWidth>
            </field>
          </fields>
        </register>
      </registers>
    </peripheral>
    <peripheral>
      <name>DMA1</name>
      <baseAddress>0x40026000</baseAddress>
      <registers>
        <register>
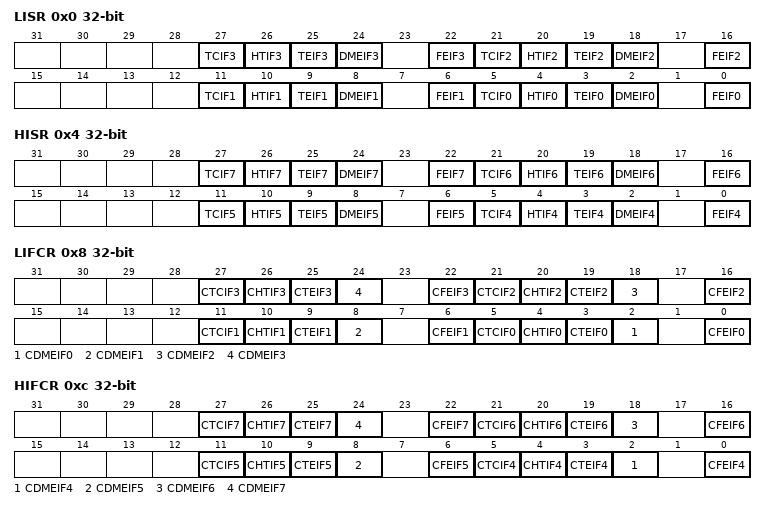
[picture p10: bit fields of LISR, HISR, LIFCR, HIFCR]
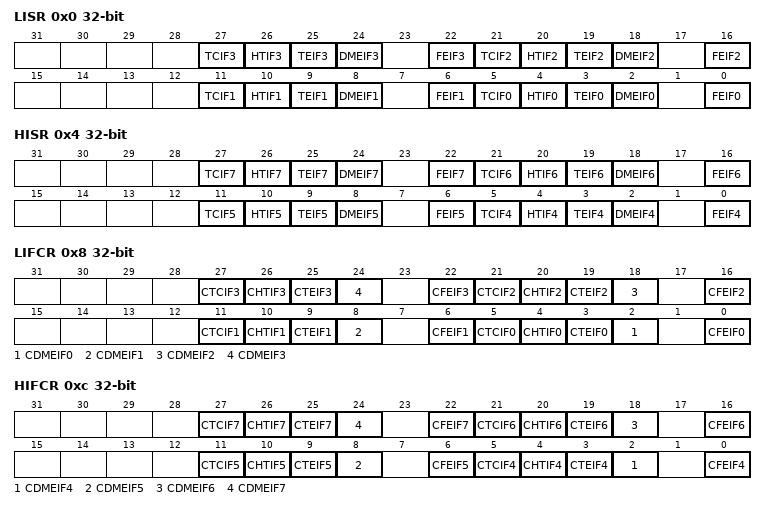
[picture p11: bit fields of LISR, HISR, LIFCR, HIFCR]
          <name>LISR</name>
          <addressOffset>0x0</addressOffset>
          <size>0x20</size>
          <fields>
            <field>
              <name>FEIF0</name>
              <bitOffset>0</bitOffset>
              <bitWidth>1</bitWidth>
            </field>
            <field>
              <name>DMEIF0</name>
              <bitOffset>2</bitOffset>
              <bitWidth>1</bitWidth>
            </field>
            <field>
              <name>TEIF0</name>
              <bitOffset>3</bitOffset>
              <bitWidth>1</bitWidth>
            </field>
            <field>
              <name>HTIF0</name>
              <bitOffset>4</bitOffset>
              <bitWidth>1</bitWidth>
            </field>
            <field>
              <name>TCIF0</name>
              <bitOffset>5</bitOffset>
              <bitWidth>1</bitWidth>
            </field>
            <field>
              <name>FEIF1</name>
              <bitOffset>6</bitOffset>
              <bitWidth>1</bitWidth>
            </field>
            <field>
              <name>DMEIF1</name>
              <bitOffset>8</bitOffset>
              <bitWidth>1</bitWidth>
            </field>
            <field>
              <name>TEIF1</name>
              <bitOffset>9</bitOffset>
              <bitWidth>1</bitWidth>
            </field>
            <field>
              <name>HTIF1</name>
              <bitOffset>10</bitOffset>
              <bitWidth>1</bitWidth>
            </field>
            <field>
              <name>TCIF1</name>
              <bitOffset>11</bitOffset>
              <bitWidth>1</bitWidth>
            </field>
            <field>
              <name>FEIF2</name>
              <bitOffset>16</bitOffset>
              <bitWidth>1</bitWidth>
            </field>
            <field>
              <name>DMEIF2</name>
              <bitOffset>18</bitOffset>
              <bitWidth>1</bitWidth>
            </field>
            <field>
              <name>TEIF2</name>
              <bitOffset>19</bitOffset>
              <bitWidth>1</bitWidth>
            </field>
            <field>
              <name>HTIF2</name>
              <bitOffset>20</bitOffset>
              <bitWidth>1</bitWidth>
            </field>
            <field>
              <name>TCIF2</name>
              <bitOffset>21</bitOffset>
              <bitWidth>1</bitWidth>
            </field>
            <field>
              <name>FEIF3</name>
              <bitOffset>22</bitOffset>
              <bitWidth>1</bitWidth>
            </field>
            <field>
              <name>DMEIF3</name>
              <bitOffset>24</bitOffset>
              <bitWidth>1</bitWidth>
            </field>
            <field>
              <name>TEIF3</name>
              <bitOffset>25</bitOffset>
              <bitWidth>1</bitWidth>
            </field>
            <field>
              <name>HTIF3</name>
              <bitOffset>26</bitOffset>
              <bitWidth>1</bitWidth>
            </field>
            <field>
              <name>TCIF3</name>
              <bitOffset>27</bitOffset>
              <bitWidth>1</bitWidth>
            </field>
          </fields>
        </register>
        <register>
          <name>HISR</name>
          <addressOffset>0x4</addressOffset>
          <size>0x20</size>
          <fields>
            <field>
              <name>FEIF4</name>
              <bitOffset>0</bitOffset>
              <bitWidth>1</bitWidth>
            </field>
            <field>
              <name>DMEIF4</name>
              <bitOffset>2</bitOffset>
              <bitWidth>1</bitWidth>
            </field>
            <field>
              <name>TEIF4</name>
              <bitOffset>3</bitOffset>
              <bitWidth>1</bitWidth>
            </field>
            <field>
              <name>HTIF4</name>
              <bitOffset>4</bitOffset>
              <bitWidth>1</bitWidth>
            </field>
            <field>
              <name>TCIF4</name>
              <bitOffset>5</bitOffset>
              <bitWidth>1</bitWidth>
            </field>
            <field>
              <name>FEIF5</name>
              <bitOffset>6</bitOffset>
              <bitWidth>1</bitWidth>
            </field>
            <field>
              <name>DMEIF5</name>
              <bitOffset>8</bitOffset>
              <bitWidth>1</bitWidth>
            </field>
            <field>
              <name>TEIF5</name>
              <bitOffset>9</bitOffset>
              <bitWidth>1</bitWidth>
            </field>
            <field>
              <name>HTIF5</name>
              <bitOffset>10</bitOffset>
              <bitWidth>1</bitWidth>
            </field>
            <field>
              <name>TCIF5</name>
              <bitOffset>11</bitOffset>
              <bitWidth>1</bitWidth>
            </field>
            <field>
              <name>FEIF6</name>
              <bitOffset>16</bitOffset>
              <bitWidth>1</bitWidth>
            </field>
            <field>
              <name>DMEIF6</name>
              <bitOffset>18</bitOffset>
              <bitWidth>1</bitWidth>
            </field>
            <field>
              <name>TEIF6</name>
              <bitOffset>19</bitOffset>
              <bitWidth>1</bitWidth>
            </field>
            <field>
              <name>HTIF6</name>
              <bitOffset>20</bitOffset>
              <bitWidth>1</bitWidth>
            </field>
            <field>
              <name>TCIF6</name>
              <bitOffset>21</bitOffset>
              <bitWidth>1</bitWidth>
            </field>
            <field>
              <name>FEIF7</name>
              <bitOffset>22</bitOffset>
              <bitWidth>1</bitWidth>
            </field>
            <field>
              <name>DMEIF7</name>
              <bitOffset>24</bitOffset>
              <bitWidth>1</bitWidth>
            </field>
            <field>
              <name>TEIF7</name>
              <bitOffset>25</bitOffset>
              <bitWidth>1</bitWidth>
            </field>
            <field>
              <name>HTIF7</name>
              <bitOffset>26</bitOffset>
              <bitWidth>1</bitWidth>
            </field>
            <field>
              <name>TCIF7</name>
              <bitOffset>27</bitOffset>
              <bitWidth>1</bitWidth>
            </field>
          </fields>
        </register>
        <register>
          <name>LIFCR</name>
          <addressOffset>0x8</addressOffset>
          <size>0x20</size>
          <fields>
            <field>
              <name>CFEIF0</name>
              <bitOffset>0</bitOffset>
              <bitWidth>1</bitWidth>
            </field>
            <field>
              <name>CDMEIF0</name>
              <bitOffset>2</bitOffset>
              <bitWidth>1</bitWidth>
            </field>
            <field>
              <name>CTEIF0</name>
              <bitOffset>3</bitOffset>
              <bitWidth>1</bitWidth>
            </field>
            <field>
              <name>CHTIF0</name>
              <bitOffset>4</bitOffset>
              <bitWidth>1</bitWidth>
            </field>
            <field>
              <name>CTCIF0</name>
              <bitOffset>5</bitOffset>
              <bitWidth>1</bitWidth>
            </field>
            <field>
              <name>CFEIF1</name>
              <bitOffset>6</bitOffset>
              <bitWidth>1</bitWidth>
            </field>
            <field>
              <name>CDMEIF1</name>
              <bitOffset>8</bitOffset>
              <bitWidth>1</bitWidth>
            </field>
            <field>
              <name>CTEIF1</name>
              <bitOffset>9</bitOffset>
              <bitWidth>1</bitWidth>
            </field>
            <field>
              <name>CHTIF1</name>
              <bitOffset>10</bitOffset>
              <bitWidth>1</bitWidth>
            </field>
            <field>
              <name>CTCIF1</name>
              <bitOffset>11</bitOffset>
              <bitWidth>1</bitWidth>
            </field>
            <field>
              <name>CFEIF2</name>
              <bitOffset>16</bitOffset>
              <bitWidth>1</bitWidth>
            </field>
            <field>
              <name>CDMEIF2</name>
              <bitOffset>18</bitOffset>
              <bitWidth>1</bitWidth>
            </field>
            <field>
              <name>CTEIF2</name>
              <bitOffset>19</bitOffset>
              <bitWidth>1</bitWidth>
            </field>
            <field>
              <name>CHTIF2</name>
              <bitOffset>20</bitOffset>
              <bitWidth>1</bitWidth>
            </field>
            <field>
              <name>CTCIF2</name>
              <bitOffset>21</bitOffset>
              <bitWidth>1</bitWidth>
            </field>
            <field>
              <name>CFEIF3</name>
              <bitOffset>22</bitOffset>
              <bitWidth>1</bitWidth>
            </field>
            <field>
              <name>CDMEIF3</name>
              <bitOffset>24</bitOffset>
              <bitWidth>1</bitWidth>
            </field>
            <field>
              <name>CTEIF3</name>
              <bitOffset>25</bitOffset>
              <bitWidth>1</bitWidth>
            </field>
            <field>
              <name>CHTIF3</name>
              <bitOffset>26</bitOffset>
              <bitWidth>1</bitWidth>
            </field>
            <field>
              <name>CTCIF3</name>
              <bitOffset>27</bitOffset>
              <bitWidth>1</bitWidth>
            </field>
          </fields>
        </register>
        <register>
          <name>HIFCR</name>
          <addressOffset>0xc</addressOffset>
          <size>0x20</size>
          <fields>
            <field>
              <name>CFEIF4</name>
              <bitOffset>0</bitOffset>
              <bitWidth>1</bitWidth>
            </field>
            <field>
              <name>CDMEIF4</name>
              <bitOffset>2</bitOffset>
              <bitWidth>1</bitWidth>
            </field>
            <field>
              <name>CTEIF4</name>
              <bitOffset>3</bitOffset>
              <bitWidth>1</bitWidth>
            </field>
            <field>
              <name>CHTIF4</name>
              <bitOffset>4</bitOffset>
              <bitWidth>1</bitWidth>
            </field>
            <field>
              <name>CTCIF4</name>
              <bitOffset>5</bitOffset>
              <bitWidth>1</bitWidth>
            </field>
            <field>
              <name>CFEIF5</name>
              <bitOffset>6</bitOffset>
              <bitWidth>1</bitWidth>
            </field>
            <field>
              <name>CDMEIF5</name>
              <bitOffset>8</bitOffset>
              <bitWidth>1</bitWidth>
            </field>
            <field>
              <name>CTEIF5</name>
              <bitOffset>9</bitOffset>
              <bitWidth>1</bitWidth>
            </field>
            <field>
              <name>CHTIF5</name>
              <bitOffset>10</bitOffset>
              <bitWidth>1</bitWidth>
            </field>
            <field>
              <name>CTCIF5</name>
              <bitOffset>11</bitOffset>
              <bitWidth>1</bitWidth>
            </field>
            <field>
              <name>CFEIF6</name>
              <bitOffset>16</bitOffset>
              <bitWidth>1</bitWidth>
            </field>
            <field>
              <name>CDMEIF6</name>
              <bitOffset>18</bitOffset>
              <bitWidth>1</bitWidth>
            </field>
            <field>
              <name>CTEIF6</name>
              <bitOffset>19</bitOffset>
              <bitWidth>1</bitWidth>
            </field>
            <field>
              <name>CHTIF6</name>
              <bitOffset>20</bitOffset>
              <bitWidth>1</bitWidth>
            </field>
            <field>
              <name>CTCIF6</name>
              <bitOffset>21</bitOffset>
              <bitWidth>1</bitWidth>
            </field>
            <field>
              <name>CFEIF7</name>
              <bitOffset>22</bitOffset>
              <bitWidth>1</bitWidth>
            </field>
            <field>
              <name>CDMEIF7</name>
              <bitOffset>24</bitOffset>
              <bitWidth>1</bitWidth>
            </field>
            <field>
              <name>CTEIF7</name>
              <bitOffset>25</bitOffset>
              <bitWidth>1</bitWidth>
            </field>
            <field>
              <name>CHTIF7</name>
              <bitOffset>26</bitOffset>
              <bitWidth>1</bitWidth>
            </field>
            <field>
              <name>CTCIF7</name>
              <bitOffset>27</bitOffset>
              <bitWidth>1</bitWidth>
            </field>
          </fields>
        </register>
        <register>
          <name>CR0</name>
          <addressOffset>0x10</addressOffset>
          <size>0x20</size>
        </register>
        <register>
          <name>CR0</name>
          <addressOffset>0x10</addressOffset>
          <size>0x20</size>
        </register>
        <register>
          <name>NDTR0</name>
          <addressOffset>0x14</addressOffset>
          <size>0x20</size>
        </register>
        <register>
          <name>NDTR0</name>
          <addressOffset>0x14</addressOffset>
          <size>0x20</size>
        </register>
        <register>
          <name>PAR0</name>
          <addressOffset>0x18</addressOffset>
          <size>0x20</size>
        </register>
        <register>
          <name>PAR0</name>
          <addressOffset>0x18</addressOffset>
          <size>0x20</size>
        </register>
        <register>
          <name>M0AR0</name>
          <addressOffset>0x1c</addressOffset>
          <size>0x20</size>
        </register>
        <register>
          <name>M0AR0</name>
          <addressOffset>0x1c</addressOffset>
          <size>0x20</size>
        </register>
        <register>
          <name>M1AR0</name>
          <addressOffset>0x20</addressOffset>
          <size>0x20</size>
        </register>
        <register>
          <name>M1AR0</name>
          <addressOffset>0x20</addressOffset>
          <size>0x20</size>
        </register>
        <register>
          <name>FCR0</name>
          <addressOffset>0x24</addressOffset>
          <size>0x20</size>
        </register>
        <register>
          <name>FCR0</name>
          <addressOffset>0x24</addressOffset>
          <size>0x20</size>
        </register>
        <register>
          <name>CR1</name>
          <addressOffset>0x28</addressOffset>
          <size>0x20</size>
        </register>
        <register>
          <name>CR1</name>
          <addressOffset>0x28</addressOffset>
          <size>0x20</size>
        </register>
        <register>
          <name>NDTR1</name>
          <addressOffset>0x2c</addressOffset>
          <size>0x20</size>
        </register>
        <register>
          <name>NDTR1</name>
          <addressOffset>0x2c</addressOffset>
          <size>0x20</size>
        </register>
        <register>
          <name>PAR1</name>
          <addressOffset>0x30</addressOffset>
          <size>0x20</size>
        </register>
        <register>
          <name>PAR1</name>
          <addressOffset>0x30</addressOffset>
          <size>0x20</size>
        </register>
        <register>
          <name>M0AR1</name>
          <addressOffset>0x34</addressOffset>
          <size>0x20</size>
        </register>
        <register>
          <name>M0AR1</name>
          <addressOffset>0x34</addressOffset>
          <size>0x20</size>
        </register>
        <register>
          <name>M1AR1</name>
          <addressOffset>0x38</addressOffset>
          <size>0x20</size>
        </register>
        <register>
          <name>M1AR1</name>
          <addressOffset>0x38</addressOffset>
          <size>0x20</size>
        </register>
        <register>
          <name>FCR1</name>
          <addressOffset>0x3c</addressOffset>
          <size>0x20</size>
        </register>
        <register>
          <name>FCR1</name>
          <addressOffset>0x3c</addressOffset>
          <size>0x20</size>
        </register>
        <register>
          <name>CR2</name>
          <addressOffset>0x40</addressOffset>
          <size>0x20</size>
        </register>
        <register>
          <name>CR2</name>
          <addressOffset>0x40</addressOffset>
          <size>0x20</size>
        </register>
        <register>
          <name>NDTR2</name>
          <addressOffset>0x44</addressOffset>
          <size>0x20</size>
        </register>
        <register>
          <name>NDTR2</name>
          <addressOffset>0x44</addressOffset>
          <size>0x20</size>
        </register>
        <register>
          <name>PAR2</name>
          <addressOffset>0x48</addressOffset>
          <size>0x20</size>
        </register>
        <register>
          <name>PAR2</name>
          <addressOffset>0x48</addressOffset>
          <size>0x20</size>
        </register>
        <register>
          <name>M0AR2</name>
          <addressOffset>0x4c</addressOffset>
          <size>0x20</size>
        </register>
        <register>
          <name>M0AR2</name>
          <addressOffset>0x4c</addressOffset>
          <size>0x20</size>
        </register>
        <register>
          <name>M1AR2</name>
          <addressOffset>0x50</addressOffset>
          <size>0x20</size>
        </register>
        <register>
          <name>M1AR2</name>
          <addressOffset>0x50</addressOffset>
          <size>0x20</size>
        </register>
        <register>
          <name>FCR2</name>
          <addressOffset>0x54</addressOffset>
          <size>0x20</size>
        </register>
        <register>
          <name>FCR2</name>
          <addressOffset>0x54</addressOffset>
          <size>0x20</size>
        </register>
        <register>
          <name>CR3</name>
          <addressOffset>0x58</addressOffset>
          <size>0x20</size>
        </register>
        <register>
          <name>CR3</name>
          <addressOffset>0x58</addressOffset>
          <size>0x20</size>
        </register>
        <register>
          <name>NDTR3</name>
          <addressOffset>0x5c</addressOffset>
          <size>0x20</size>
        </register>
        <register>
          <name>NDTR3</name>
          <addressOffset>0x5c</addressOffset>
          <size>0x20</size>
        </register>
        <register>
          <name>PAR3</name>
          <addressOffset>0x60</addressOffset>
          <size>0x20</size>
        </register>
        <register>
          <name>PAR3</name>
          <addressOffset>0x60</addressOffset>
          <size>0x20</size>
        </register>
        <register>
          <name>M0AR3</name>
          <addressOffset>0x64</addressOffset>
          <size>0x20</size>
        </register>
        <register>
          <name>M0AR3</name>
          <addressOffset>0x64</addressOffset>
          <size>0x20</size>
        </register>
        <register>
          <name>M1AR3</name>
          <addressOffset>0x68</addressOffset>
          <size>0x20</size>
        </register>
        <register>
          <name>M1AR3</name>
          <addressOffset>0x68</addressOffset>
          <size>0x20</size>
        </register>
        <register>
          <name>FCR3</name>
          <addressOffset>0x6c</addressOffset>
          <size>0x20</size>
        </register>
        <register>
          <name>FCR3</name>
          <addressOffset>0x6c</addressOffset>
          <size>0x20</size>
        </register>
        <register>
          <name>CR4</name>
          <addressOffset>0x70</addressOffset>
          <size>0x20</size>
        </register>
        <register>
          <name>CR4</name>
          <addressOffset>0x70</addressOffset>
          <size>0x20</size>
        </register>
        <register>
          <name>NDTR4</name>
          <addressOffset>0x74</addressOffset>
          <size>0x20</size>
        </register>
        <register>
          <name>NDTR4</name>
          <addressOffset>0x74</addressOffset>
          <size>0x20</size>
        </register>
        <register>
          <name>PAR4</name>
          <addressOffset>0x78</addressOffset>
          <size>0x20</size>
        </register>
        <register>
          <name>PAR4</name>
          <addressOffset>0x78</addressOffset>
          <size>0x20</size>
        </register>
        <register>
          <name>M0AR4</name>
          <addressOffset>0x7c</addressOffset>
          <size>0x20</size>
        </register>
        <register>
          <name>M0AR4</name>
          <addressOffset>0x7c</addressOffset>
          <size>0x20</size>
        </register>
        <register>
          <name>M1AR4</name>
          <addressOffset>0x80</addressOffset>
          <size>0x20</size>
        </register>
        <register>
          <name>M1AR4</name>
          <addressOffset>0x80</addressOffset>
          <size>0x20</size>
        </register>
        <register>
          <name>FCR4</name>
          <addressOffset>0x84</addressOffset>
          <size>0x20</size>
        </register>
        <register>
          <name>FCR4</name>
          <addressOffset>0x84</addressOffset>
          <size>0x20</size>
        </register>
        <register>
          <name>CR5</name>
          <addressOffset>0x88</addressOffset>
          <size>0x20</size>
        </register>
        <register>
          <name>CR5</name>
          <addressOffset>0x88</addressOffset>
          <size>0x20</size>
        </register>
        <register>
          <name>NDTR5</name>
          <addressOffset>0x8c</addressOffset>
          <size>0x20</size>
        </register>
        <register>
          <name>NDTR5</name>
          <addressOffset>0x8c</addressOffset>
          <size>0x20</size>
        </register>
        <register>
          <name>PAR5</name>
          <addressOffset>0x90</addressOffset>
          <size>0x20</size>
        </register>
        <register>
          <name>PAR5</name>
          <addressOffset>0x90</addressOffset>
          <size>0x20</size>
        </register>
        <register>
          <name>M0AR5</name>
          <addressOffset>0x94</addressOffset>
          <size>0x20</size>
        </register>
        <register>
          <name>M0AR5</name>
          <addressOffset>0x94</addressOffset>
          <size>0x20</size>
        </register>
        <register>
          <name>M1AR5</name>
          <addressOffset>0x98</addressOffset>
          <size>0x20</size>
        </register>
        <register>
          <name>M1AR5</name>
          <addressOffset>0x98</addressOffset>
          <size>0x20</size>
        </register>
        <register>
          <name>FCR5</name>
          <addressOffset>0x9c</addressOffset>
          <size>0x20</size>
        </register>
        <register>
          <name>FCR5</name>
          <addressOffset>0x9c</addressOffset>
          <size>0x20</size>
        </register>
        <register>
          <name>CR6</name>
          <addressOffset>0xa0</addressOffset>
          <size>0x20</size>
        </register>
        <register>
          <name>CR6</name>
          <addressOffset>0xa0</addressOffset>
          <size>0x20</size>
        </register>
        <register>
          <name>NDTR6</name>
          <addressOffset>0xa4</addressOffset>
          <size>0x20</size>
        </register>
        <register>
          <name>NDTR6</name>
          <addressOffset>0xa4</addressOffset>
          <size>0x20</size>
        </register>
        <register>
          <name>PAR6</name>
          <addressOffset>0xa8</addressOffset>
          <size>0x20</size>
        </register>
        <register>
          <name>PAR6</name>
          <addressOffset>0xa8</addressOffset>
          <size>0x20</size>
        </register>
        <register>
          <name>M0AR6</name>
          <addressOffset>0xac</addressOffset>
          <size>0x20</size>
        </register>
        <register>
          <name>M0AR6</name>
          <addressOffset>0xac</addressOffset>
          <size>0x20</size>
        </register>
        <register>
          <name>M1AR6</name>
          <addressOffset>0xb0</addressOffset>
          <size>0x20</size>
        </register>
        <register>
          <name>M1AR6</name>
          <addressOffset>0xb0</addressOffset>
          <size>0x20</size>
        </register>
        <register>
          <name>FCR6</name>
          <addressOffset>0xb4</addressOffset>
          <size>0x20</size>
        </register>
        <register>
          <name>FCR6</name>
          <addressOffset>0xb4</addressOffset>
          <size>0x20</size>
        </register>
        <register>
          <name>CR7</name>
          <addressOffset>0xb8</addressOffset>
          <size>0x20</size>
        </register>
        <register>
          <name>CR7</name>
          <addressOffset>0xb8</addressOffset>
          <size>0x20</size>
        </register>
        <register>
          <name>NDTR7</name>
          <addressOffset>0xbc</addressOffset>
          <size>0x20</size>
        </register>
        <register>
          <name>NDTR7</name>
          <addressOffset>0xbc</addressOffset>
          <size>0x20</size>
        </register>
        <register>
          <name>PAR7</name>
          <addressOffset>0xc0</addressOffset>
          <size>0x20</size>
        </register>
        <register>
          <name>PAR7</name>
          <addressOffset>0xc0</addressOffset>
          <size>0x20</size>
        </register>
        <register>
          <name>M0AR7</name>
          <addressOffset>0xc4</addressOffset>
          <size>0x20</size>
        </register>
        <register>
          <name>M0AR7</name>
          <addressOffset>0xc4</addressOffset>
          <size>0x20</size>
        </register>
        <register>
          <name>M1AR7</name>
          <addressOffset>0xc8</addressOffset>
          <size>0x20</size>
        </register>
        <register>
          <name>M1AR7</name>
          <addressOffset>0xc8</addressOffset>
          <size>0x20</size>
        </register>
        <register>
          <name>FCR7</name>
          <addressOffset>0xcc</addressOffset>
          <size>0x20</size>
        </register>
        <register>
          <name>FCR7</name>
          <addressOffset>0xcc</addressOffset>
          <size>0x20</size>
        </register>
      </registers>
    </peripheral>
    <peripheral>
      <name>DMA2</name>
      <baseAddress>0x40026400</baseAddress>
      <registers>
        <register>
          <name>LISR</name>
          <addressOffset>0x0</addressOffset>
          <size>0x20</size>
          <fields>
            <field>
              <name>FEIF0</name>
              <bitOffset>0</bitOffset>
              <bitWidth>1</bitWidth>
            </field>
            <field>
              <name>DMEIF0</name>
              <bitOffset>2</bitOffset>
              <bitWidth>1</bitWidth>
            </field>
            <field>
              <name>TEIF0</name>
              <bitOffset>3</bitOffset>
              <bitWidth>1</bitWidth>
            </field>
            <field>
              <name>HTIF0</name>
              <bitOffset>4</bitOffset>
              <bitWidth>1</bitWidth>
            </field>
            <field>
              <name>TCIF0</name>
              <bitOffset>5</bitOffset>
              <bitWidth>1</bitWidth>
            </field>
            <field>
              <name>FEIF1</name>
              <bitOffset>6</bitOffset>
              <bitWidth>1</bitWidth>
            </field>
            <field>
              <name>DMEIF1</name>
              <bitOffset>8</bitOffset>
              <bitWidth>1</bitWidth>
            </field>
            <field>
              <name>TEIF1</name>
              <bitOffset>9</bitOffset>
              <bitWidth>1</bitWidth>
            </field>
            <field>
              <name>HTIF1</name>
              <bitOffset>10</bitOffset>
              <bitWidth>1</bitWidth>
            </field>
            <field>
              <name>TCIF1</name>
              <bitOffset>11</bitOffset>
              <bitWidth>1</bitWidth>
            </field>
            <field>
              <name>FEIF2</name>
              <bitOffset>16</bitOffset>
              <bitWidth>1</bitWidth>
            </field>
            <field>
              <name>DMEIF2</name>
              <bitOffset>18</bitOffset>
              <bitWidth>1</bitWidth>
            </field>
            <field>
              <name>TEIF2</name>
              <bitOffset>19</bitOffset>
              <bitWidth>1</bitWidth>
            </field>
            <field>
              <name>HTIF2</name>
              <bitOffset>20</bitOffset>
              <bitWidth>1</bitWidth>
            </field>
            <field>
              <name>TCIF2</name>
              <bitOffset>21</bitOffset>
              <bitWidth>1</bitWidth>
            </field>
            <field>
              <name>FEIF3</name>
              <bitOffset>22</bitOffset>
              <bitWidth>1</bitWidth>
            </field>
            <field>
              <name>DMEIF3</name>
              <bitOffset>24</bitOffset>
              <bitWidth>1</bitWidth>
            </field>
            <field>
              <name>TEIF3</name>
              <bitOffset>25</bitOffset>
              <bitWidth>1</bitWidth>
            </field>
            <field>
              <name>HTIF3</name>
              <bitOffset>26</bitOffset>
              <bitWidth>1</bitWidth>
            </field>
            <field>
              <name>TCIF3</name>
              <bitOffset>27</bitOffset>
              <bitWidth>1</bitWidth>
            </field>
          </fields>
        </register>
        <register>
          <name>HISR</name>
          <addressOffset>0x4</addressOffset>
          <size>0x20</size>
          <fields>
            <field>
              <name>FEIF4</name>
              <bitOffset>0</bitOffset>
              <bitWidth>1</bitWidth>
            </field>
            <field>
              <name>DMEIF4</name>
              <bitOffset>2</bitOffset>
              <bitWidth>1</bitWidth>
            </field>
            <field>
              <name>TEIF4</name>
              <bitOffset>3</bitOffset>
              <bitWidth>1</bitWidth>
            </field>
            <field>
              <name>HTIF4</name>
              <bitOffset>4</bitOffset>
              <bitWidth>1</bitWidth>
            </field>
            <field>
              <name>TCIF4</name>
              <bitOffset>5</bitOffset>
              <bitWidth>1</bitWidth>
            </field>
            <field>
              <name>FEIF5</name>
              <bitOffset>6</bitOffset>
              <bitWidth>1</bitWidth>
            </field>
            <field>
              <name>DMEIF5</name>
              <bitOffset>8</bitOffset>
              <bitWidth>1</bitWidth>
            </field>
            <field>
              <name>TEIF5</name>
              <bitOffset>9</bitOffset>
              <bitWidth>1</bitWidth>
            </field>
            <field>
              <name>HTIF5</name>
              <bitOffset>10</bitOffset>
              <bitWidth>1</bitWidth>
            </field>
            <field>
              <name>TCIF5</name>
              <bitOffset>11</bitOffset>
              <bitWidth>1</bitWidth>
            </field>
            <field>
              <name>FEIF6</name>
              <bitOffset>16</bitOffset>
              <bitWidth>1</bitWidth>
            </field>
            <field>
              <name>DMEIF6</name>
              <bitOffset>18</bitOffset>
              <bitWidth>1</bitWidth>
            </field>
            <field>
              <name>TEIF6</name>
              <bitOffset>19</bitOffset>
              <bitWidth>1</bitWidth>
            </field>
            <field>
              <name>HTIF6</name>
              <bitOffset>20</bitOffset>
              <bitWidth>1</bitWidth>
            </field>
            <field>
              <name>TCIF6</name>
              <bitOffset>21</bitOffset>
              <bitWidth>1</bitWidth>
            </field>
            <field>
              <name>FEIF7</name>
              <bitOffset>22</bitOffset>
              <bitWidth>1</bitWidth>
            </field>
            <field>
              <name>DMEIF7</name>
              <bitOffset>24</bitOffset>
              <bitWidth>1</bitWidth>
            </field>
            <field>
              <name>TEIF7</name>
              <bitOffset>25</bitOffset>
              <bitWidth>1</bitWidth>
            </field>
            <field>
              <name>HTIF7</name>
              <bitOffset>26</bitOffset>
              <bitWidth>1</bitWidth>
            </field>
            <field>
              <name>TCIF7</name>
              <bitOffset>27</bitOffset>
              <bitWidth>1</bitWidth>
            </field>
          </fields>
        </register>
        <register>
          <name>LIFCR</name>
          <addressOffset>0x8</addressOffset>
          <size>0x20</size>
          <fields>
            <field>
              <name>CFEIF0</name>
              <bitOffset>0</bitOffset>
              <bitWidth>1</bitWidth>
            </field>
            <field>
              <name>CDMEIF0</name>
              <bitOffset>2</bitOffset>
              <bitWidth>1</bitWidth>
            </field>
            <field>
              <name>CTEIF0</name>
              <bitOffset>3</bitOffset>
              <bitWidth>1</bitWidth>
            </field>
            <field>
              <name>CHTIF0</name>
              <bitOffset>4</bitOffset>
              <bitWidth>1</bitWidth>
            </field>
            <field>
              <name>CTCIF0</name>
              <bitOffset>5</bitOffset>
              <bitWidth>1</bitWidth>
            </field>
            <field>
              <name>CFEIF1</name>
              <bitOffset>6</bitOffset>
              <bitWidth>1</bitWidth>
            </field>
            <field>
              <name>CDMEIF1</name>
              <bitOffset>8</bitOffset>
              <bitWidth>1</bitWidth>
            </field>
            <field>
              <name>CTEIF1</name>
              <bitOffset>9</bitOffset>
              <bitWidth>1</bitWidth>
            </field>
            <field>
              <name>CHTIF1</name>
              <bitOffset>10</bitOffset>
              <bitWidth>1</bitWidth>
            </field>
            <field>
              <name>CTCIF1</name>
              <bitOffset>11</bitOffset>
              <bitWidth>1</bitWidth>
            </field>
            <field>
              <name>CFEIF2</name>
              <bitOffset>16</bitOffset>
              <bitWidth>1</bitWidth>
            </field>
            <field>
              <name>CDMEIF2</name>
              <bitOffset>18</bitOffset>
              <bitWidth>1</bitWidth>
            </field>
            <field>
              <name>CTEIF2</name>
              <bitOffset>19</bitOffset>
              <bitWidth>1</bitWidth>
            </field>
            <field>
              <name>CHTIF2</name>
              <bitOffset>20</bitOffset>
              <bitWidth>1</bitWidth>
            </field>
            <field>
              <name>CTCIF2</name>
              <bitOffset>21</bitOffset>
              <bitWidth>1</bitWidth>
            </field>
            <field>
              <name>CFEIF3</name>
              <bitOffset>22</bitOffset>
              <bitWidth>1</bitWidth>
            </field>
            <field>
              <name>CDMEIF3</name>
              <bitOffset>24</bitOffset>
              <bitWidth>1</bitWidth>
            </field>
            <field>
              <name>CTEIF3</name>
              <bitOffset>25</bitOffset>
              <bitWidth>1</bitWidth>
            </field>
            <field>
              <name>CHTIF3</name>
              <bitOffset>26</bitOffset>
              <bitWidth>1</bitWidth>
            </field>
            <field>
              <name>CTCIF3</name>
              <bitOffset>27</bitOffset>
              <bitWidth>1</bitWidth>
            </field>
          </fields>
        </register>
        <register>
          <name>HIFCR</name>
          <addressOffset>0xc</addressOffset>
          <size>0x20</size>
          <fields>
            <field>
              <name>CFEIF4</name>
              <bitOffset>0</bitOffset>
              <bitWidth>1</bitWidth>
            </field>
            <field>
              <name>CDMEIF4</name>
              <bitOffset>2</bitOffset>
              <bitWidth>1</bitWidth>
            </field>
            <field>
              <name>CTEIF4</name>
              <bitOffset>3</bitOffset>
              <bitWidth>1</bitWidth>
            </field>
            <field>
              <name>CHTIF4</name>
              <bitOffset>4</bitOffset>
              <bitWidth>1</bitWidth>
            </field>
            <field>
              <name>CTCIF4</name>
              <bitOffset>5</bitOffset>
              <bitWidth>1</bitWidth>
            </field>
            <field>
              <name>CFEIF5</name>
              <bitOffset>6</bitOffset>
              <bitWidth>1</bitWidth>
            </field>
            <field>
              <name>CDMEIF5</name>
              <bitOffset>8</bitOffset>
              <bitWidth>1</bitWidth>
            </field>
            <field>
              <name>CTEIF5</name>
              <bitOffset>9</bitOffset>
              <bitWidth>1</bitWidth>
            </field>
            <field>
              <name>CHTIF5</name>
              <bitOffset>10</bitOffset>
              <bitWidth>1</bitWidth>
            </field>
            <field>
              <name>CTCIF5</name>
              <bitOffset>11</bitOffset>
              <bitWidth>1</bitWidth>
            </field>
            <field>
              <name>CFEIF6</name>
              <bitOffset>16</bitOffset>
              <bitWidth>1</bitWidth>
            </field>
            <field>
              <name>CDMEIF6</name>
              <bitOffset>18</bitOffset>
              <bitWidth>1</bitWidth>
            </field>
            <field>
              <name>CTEIF6</name>
              <bitOffset>19</bitOffset>
              <bitWidth>1</bitWidth>
            </field>
            <field>
              <name>CHTIF6</name>
              <bitOffset>20</bitOffset>
              <bitWidth>1</bitWidth>
            </field>
            <field>
              <name>CTCIF6</name>
              <bitOffset>21</bitOffset>
              <bitWidth>1</bitWidth>
            </field>
            <field>
              <name>CFEIF7</name>
              <bitOffset>22</bitOffset>
              <bitWidth>1</bitWidth>
            </field>
            <field>
              <name>CDMEIF7</name>
              <bitOffset>24</bitOffset>
              <bitWidth>1</bitWidth>
            </field>
            <field>
              <name>CTEIF7</name>
              <bitOffset>25</bitOffset>
              <bitWidth>1</bitWidth>
            </field>
            <field>
              <name>CHTIF7</name>
              <bitOffset>26</bitOffset>
              <bitWidth>1</bitWidth>
            </field>
            <field>
              <name>CTCIF7</name>
              <bitOffset>27</bitOffset>
              <bitWidth>1</bitWidth>
            </field>
          </fields>
        </register>
        <register>
          <name>CR0</name>
          <addressOffset>0x10</addressOffset>
          <size>0x20</size>
        </register>
        <register>
          <name>CR0</name>
          <addressOffset>0x10</addressOffset>
          <size>0x20</size>
        </register>
        <register>
          <name>NDTR0</name>
          <addressOffset>0x14</addressOffset>
          <size>0x20</size>
        </register>
        <register>
          <name>NDTR0</name>
          <addressOffset>0x14</addressOffset>
          <size>0x20</size>
        </register>
        <register>
          <name>PAR0</name>
          <addressOffset>0x18</addressOffset>
          <size>0x20</size>
        </register>
        <register>
          <name>PAR0</name>
          <addressOffset>0x18</addressOffset>
          <size>0x20</size>
        </register>
        <register>
          <name>M0AR0</name>
          <addressOffset>0x1c</addressOffset>
          <size>0x20</size>
        </register>
        <register>
          <name>M0AR0</name>
          <addressOffset>0x1c</addressOffset>
          <size>0x20</size>
        </register>
        <register>
          <name>M1AR0</name>
          <addressOffset>0x20</addressOffset>
          <size>0x20</size>
        </register>
        <register>
          <name>M1AR0</name>
          <addressOffset>0x20</addressOffset>
          <size>0x20</size>
        </register>
        <register>
          <name>FCR0</name>
          <addressOffset>0x24</addressOffset>
          <size>0x20</size>
        </register>
        <register>
          <name>FCR0</name>
          <addressOffset>0x24</addressOffset>
          <size>0x20</size>
        </register>
        <register>
          <name>CR1</name>
          <addressOffset>0x28</addressOffset>
          <size>0x20</size>
        </register>
        <register>
          <name>CR1</name>
          <addressOffset>0x28</addressOffset>
          <size>0x20</size>
        </register>
        <register>
          <name>NDTR1</name>
          <addressOffset>0x2c</addressOffset>
          <size>0x20</size>
        </register>
        <register>
          <name>NDTR1</name>
          <addressOffset>0x2c</addressOffset>
          <size>0x20</size>
        </register>
        <register>
          <name>PAR1</name>
          <addressOffset>0x30</addressOffset>
          <size>0x20</size>
        </register>
        <register>
          <name>PAR1</name>
          <addressOffset>0x30</addressOffset>
          <size>0x20</size>
        </register>
        <register>
          <name>M0AR1</name>
          <addressOffset>0x34</addressOffset>
          <size>0x20</size>
        </register>
        <register>
          <name>M0AR1</name>
          <addressOffset>0x34</addressOffset>
          <size>0x20</size>
        </register>
        <register>
          <name>M1AR1</name>
          <addressOffset>0x38</addressOffset>
          <size>0x20</size>
        </register>
        <register>
          <name>M1AR1</name>
          <addressOffset>0x38</addressOffset>
          <size>0x20</size>
        </register>
        <register>
          <name>FCR1</name>
          <addressOffset>0x3c</addressOffset>
          <size>0x20</size>
        </register>
        <register>
          <name>FCR1</name>
          <addressOffset>0x3c</addressOffset>
          <size>0x20</size>
        </register>
        <register>
          <name>CR2</name>
          <addressOffset>0x40</addressOffset>
          <size>0x20</size>
        </register>
        <register>
          <name>CR2</name>
          <addressOffset>0x40</addressOffset>
          <size>0x20</size>
        </register>
        <register>
          <name>NDTR2</name>
          <addressOffset>0x44</addressOffset>
          <size>0x20</size>
        </register>
        <register>
          <name>NDTR2</name>
          <addressOffset>0x44</addressOffset>
          <size>0x20</size>
        </register>
        <register>
          <name>PAR2</name>
          <addressOffset>0x48</addressOffset>
          <size>0x20</size>
        </register>
        <register>
          <name>PAR2</name>
          <addressOffset>0x48</addressOffset>
          <size>0x20</size>
        </register>
        <register>
          <name>M0AR2</name>
          <addressOffset>0x4c</addressOffset>
          <size>0x20</size>
        </register>
        <register>
          <name>M0AR2</name>
          <addressOffset>0x4c</addressOffset>
          <size>0x20</size>
        </register>
        <register>
          <name>M1AR2</name>
          <addressOffset>0x50</addressOffset>
          <size>0x20</size>
        </register>
        <register>
          <name>M1AR2</name>
          <addressOffset>0x50</addressOffset>
          <size>0x20</size>
        </register>
        <register>
          <name>FCR2</name>
          <addressOffset>0x54</addressOffset>
          <size>0x20</size>
        </register>
        <register>
          <name>FCR2</name>
          <addressOffset>0x54</addressOffset>
          <size>0x20</size>
        </register>
        <register>
          <name>CR3</name>
          <addressOffset>0x58</addressOffset>
          <size>0x20</size>
        </register>
        <register>
          <name>CR3</name>
          <addressOffset>0x58</addressOffset>
          <size>0x20</size>
        </register>
        <register>
          <name>NDTR3</name>
          <addressOffset>0x5c</addressOffset>
          <size>0x20</size>
        </register>
        <register>
          <name>NDTR3</name>
          <addressOffset>0x5c</addressOffset>
          <size>0x20</size>
        </register>
        <register>
          <name>PAR3</name>
          <addressOffset>0x60</addressOffset>
          <size>0x20</size>
        </register>
        <register>
          <name>PAR3</name>
          <addressOffset>0x60</addressOffset>
          <size>0x20</size>
        </register>
        <register>
          <name>M0AR3</name>
          <addressOffset>0x64</addressOffset>
          <size>0x20</size>
        </register>
        <register>
          <name>M0AR3</name>
          <addressOffset>0x64</addressOffset>
          <size>0x20</size>
        </register>
        <register>
          <name>M1AR3</name>
          <addressOffset>0x68</addressOffset>
          <size>0x20</size>
        </register>
        <register>
          <name>M1AR3</name>
          <addressOffset>0x68</addressOffset>
          <size>0x20</size>
        </register>
        <register>
          <name>FCR3</name>
          <addressOffset>0x6c</addressOffset>
          <size>0x20</size>
        </register>
        <register>
          <name>FCR3</name>
          <addressOffset>0x6c</addressOffset>
          <size>0x20</size>
        </register>
        <register>
          <name>CR4</name>
          <addressOffset>0x70</addressOffset>
          <size>0x20</size>
        </register>
        <register>
          <name>CR4</name>
          <addressOffset>0x70</addressOffset>
          <size>0x20</size>
        </register>
        <register>
          <name>NDTR4</name>
          <addressOffset>0x74</addressOffset>
          <size>0x20</size>
        </register>
        <register>
          <name>NDTR4</name>
          <addressOffset>0x74</addressOffset>
          <size>0x20</size>
        </register>
        <register>
          <name>PAR4</name>
          <addressOffset>0x78</addressOffset>
          <size>0x20</size>
        </register>
        <register>
          <name>PAR4</name>
          <addressOffset>0x78</addressOffset>
          <size>0x20</size>
        </register>
        <register>
          <name>M0AR4</name>
          <addressOffset>0x7c</addressOffset>
          <size>0x20</size>
        </register>
        <register>
          <name>M0AR4</name>
          <addressOffset>0x7c</addressOffset>
          <size>0x20</size>
        </register>
        <register>
          <name>M1AR4</name>
          <addressOffset>0x80</addressOffset>
          <size>0x20</size>
        </register>
        <register>
          <name>M1AR4</name>
          <addressOffset>0x80</addressOffset>
          <size>0x20</size>
        </register>
        <register>
          <name>FCR4</name>
          <addressOffset>0x84</addressOffset>
          <size>0x20</size>
        </register>
        <register>
          <name>FCR4</name>
          <addressOffset>0x84</addressOffset>
          <size>0x20</size>
        </register>
        <register>
          <name>CR5</name>
          <addressOffset>0x88</addressOffset>
          <size>0x20</size>
        </register>
        <register>
          <name>CR5</name>
          <addressOffset>0x88</addressOffset>
          <size>0x20</size>
        </register>
        <register>
          <name>NDTR5</name>
          <addressOffset>0x8c</addressOffset>
          <size>0x20</size>
        </register>
        <register>
          <name>NDTR5</name>
          <addressOffset>0x8c</addressOffset>
          <size>0x20</size>
        </register>
        <register>
          <name>PAR5</name>
          <addressOffset>0x90</addressOffset>
          <size>0x20</size>
        </register>
        <register>
          <name>PAR5</name>
          <addressOffset>0x90</addressOffset>
          <size>0x20</size>
        </register>
        <register>
          <name>M0AR5</name>
          <addressOffset>0x94</addressOffset>
          <size>0x20</size>
        </register>
        <register>
          <name>M0AR5</name>
          <addressOffset>0x94</addressOffset>
          <size>0x20</size>
        </register>
        <register>
          <name>M1AR5</name>
          <addressOffset>0x98</addressOffset>
          <size>0x20</size>
        </register>
        <register>
          <name>M1AR5</name>
          <addressOffset>0x98</addressOffset>
          <size>0x20</size>
        </register>
        <register>
          <name>FCR5</name>
          <addressOffset>0x9c</addressOffset>
          <size>0x20</size>
        </register>
        <register>
          <name>FCR5</name>
          <addressOffset>0x9c</addressOffset>
          <size>0x20</size>
        </register>
        <register>
          <name>CR6</name>
          <addressOffset>0xa0</addressOffset>
          <size>0x20</size>
        </register>
        <register>
          <name>CR6</name>
          <addressOffset>0xa0</addressOffset>
          <size>0x20</size>
        </register>
        <register>
          <name>NDTR6</name>
          <addressOffset>0xa4</addressOffset>
          <size>0x20</size>
        </register>
        <register>
          <name>NDTR6</name>
          <addressOffset>0xa4</addressOffset>
          <size>0x20</size>
        </register>
        <register>
          <name>PAR6</name>
          <addressOffset>0xa8</addressOffset>
          <size>0x20</size>
        </register>
        <register>
          <name>PAR6</name>
          <addressOffset>0xa8</addressOffset>
          <size>0x20</size>
        </register>
        <register>
          <name>M0AR6</name>
          <addressOffset>0xac</addressOffset>
          <size>0x20</size>
        </register>
        <register>
          <name>M0AR6</name>
          <addressOffset>0xac</addressOffset>
          <size>0x20</size>
        </register>
        <register>
          <name>M1AR6</name>
          <addressOffset>0xb0</addressOffset>
          <size>0x20</size>
        </register>
        <register>
          <name>M1AR6</name>
          <addressOffset>0xb0</addressOffset>
          <size>0x20</size>
        </register>
        <register>
          <name>FCR6</name>
          <addressOffset>0xb4</addressOffset>
          <size>0x20</size>
        </register>
        <register>
          <name>FCR6</name>
          <addressOffset>0xb4</addressOffset>
          <size>0x20</size>
        </register>
        <register>
          <name>CR7</name>
          <addressOffset>0xb8</addressOffset>
          <size>0x20</size>
        </register>
        <register>
          <name>CR7</name>
          <addressOffset>0xb8</addressOffset>
          <size>0x20</size>
        </register>
        <register>
          <name>NDTR7</name>
          <addressOffset>0xbc</addressOffset>
          <size>0x20</size>
        </register>
        <register>
          <name>NDTR7</name>
          <addressOffset>0xbc</addressOffset>
          <size>0x20</size>
        </register>
        <register>
          <name>PAR7</name>
          <addressOffset>0xc0</addressOffset>
          <size>0x20</size>
        </register>
        <register>
          <name>PAR7</name>
          <addressOffset>0xc0</addressOffset>
          <size>0x20</size>
        </register>
        <register>
          <name>M0AR7</name>
          <addressOffset>0xc4</addressOffset>
          <size>0x20</size>
        </register>
        <register>
          <name>M0AR7</name>
          <addressOffset>0xc4</addressOffset>
          <size>0x20</size>
        </register>
        <register>
          <name>M1AR7</name>
          <addressOffset>0xc8</addressOffset>
          <size>0x20</size>
        </register>
        <register>
          <name>M1AR7</name>
          <addressOffset>0xc8</addressOffset>
          <size>0x20</size>
        </register>
        <register>
          <name>FCR7</name>
          <addressOffset>0xcc</addressOffset>
          <size>0x20</size>
        </register>
        <register>
          <name>FCR7</name>
          <addressOffset>0xcc</addressOffset>
          <size>0x20</size>
        </register>
      </registers>
    </peripheral>
    <peripheral>
      <name>USB_OTG_FS</name>
      <baseAddress>0x50000000</baseAddress>
      <registers>
        <register>
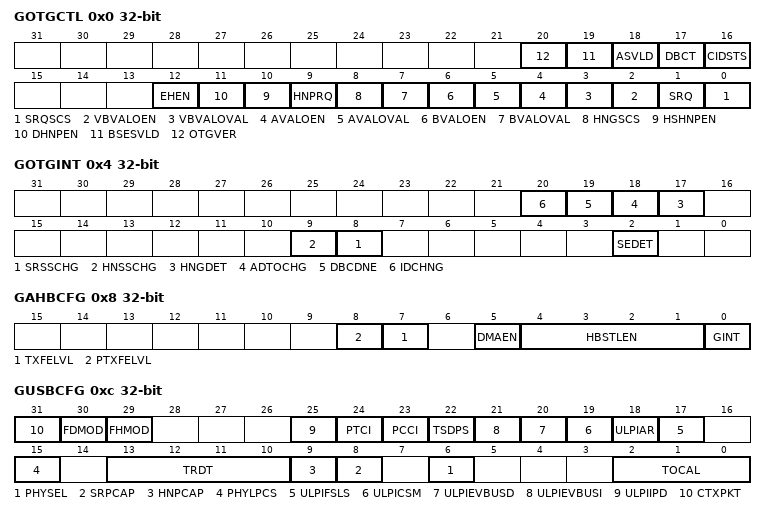
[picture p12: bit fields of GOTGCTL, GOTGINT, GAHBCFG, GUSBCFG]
          <name>GOTGCTL</name>
          <addressOffset>0x0</addressOffset>
          <size>0x20</size>
          <fields>
            <field>
              <name>SRQSCS</name>
              <bitOffset>0</bitOffset>
              <bitWidth>1</bitWidth>
            </field>
            <field>
              <name>SRQ</name>
              <bitOffset>1</bitOffset>
              <bitWidth>1</bitWidth>
            </field>
            <field>
              <name>VBVALOEN</name>
              <bitOffset>2</bitOffset>
              <bitWidth>1</bitWidth>
            </field>
            <field>
              <name>VBVALOVAL</name>
              <bitOffset>3</bitOffset>
              <bitWidth>1</bitWidth>
            </field>
            <field>
              <name>AVALOEN</name>
              <bitOffset>4</bitOffset>
              <bitWidth>1</bitWidth>
            </field>
            <field>
              <name>AVALOVAL</name>
              <bitOffset>5</bitOffset>
              <bitWidth>1</bitWidth>
            </field>
            <field>
              <name>BVALOEN</name>
              <bitOffset>6</bitOffset>
              <bitWidth>1</bitWidth>
            </field>
            <field>
              <name>BVALOVAL</name>
              <bitOffset>7</bitOffset>
              <bitWidth>1</bitWidth>
            </field>
            <field>
              <name>HNGSCS</name>
              <bitOffset>8</bitOffset>
              <bitWidth>1</bitWidth>
            </field>
            <field>
              <name>HNPRQ</name>
              <bitOffset>9</bitOffset>
              <bitWidth>1</bitWidth>
            </field>
            <field>
              <name>HSHNPEN</name>
              <bitOffset>10</bitOffset>
              <bitWidth>1</bitWidth>
            </field>
            <field>
              <name>DHNPEN</name>
              <bitOffset>11</bitOffset>
              <bitWidth>1</bitWidth>
            </field>
            <field>
              <name>EHEN</name>
              <bitOffset>12</bitOffset>
              <bitWidth>1</bitWidth>
            </field>
            <field>
              <name>CIDSTS</name>
              <bitOffset>16</bitOffset>
              <bitWidth>1</bitWidth>
            </field>
            <field>
              <name>DBCT</name>
              <bitOffset>17</bitOffset>
              <bitWidth>1</bitWidth>
            </field>
            <field>
              <name>ASVLD</name>
              <bitOffset>18</bitOffset>
              <bitWidth>1</bitWidth>
            </field>
            <field>
              <name>BSESVLD</name>
              <bitOffset>19</bitOffset>
              <bitWidth>1</bitWidth>
            </field>
            <field>
              <name>OTGVER</name>
              <bitOffset>20</bitOffset>
              <bitWidth>1</bitWidth>
            </field>
          </fields>
        </register>
        <register>
          <name>GOTGINT</name>
          <addressOffset>0x4</addressOffset>
          <size>0x20</size>
          <fields>
            <field>
              <name>SEDET</name>
              <bitOffset>2</bitOffset>
              <bitWidth>1</bitWidth>
            </field>
            <field>
              <name>SRSSCHG</name>
              <bitOffset>8</bitOffset>
              <bitWidth>1</bitWidth>
            </field>
            <field>
              <name>HNSSCHG</name>
              <bitOffset>9</bitOffset>
              <bitWidth>1</bitWidth>
            </field>
            <field>
              <name>HNGDET</name>
              <bitOffset>17</bitOffset>
              <bitWidth>1</bitWidth>
            </field>
            <field>
              <name>ADTOCHG</name>
              <bitOffset>18</bitOffset>
              <bitWidth>1</bitWidth>
            </field>
            <field>
              <name>DBCDNE</name>
              <bitOffset>19</bitOffset>
              <bitWidth>1</bitWidth>
            </field>
            <field>
              <name>IDCHNG</name>
              <bitOffset>20</bitOffset>
              <bitWidth>1</bitWidth>
            </field>
          </fields>
        </register>
        <register>
          <name>GAHBCFG</name>
          <addressOffset>0x8</addressOffset>
          <size>0x20</size>
          <fields>
            <field>
              <name>GINT</name>
              <bitOffset>0</bitOffset>
              <bitWidth>1</bitWidth>
            </field>
            <field>
              <name>HBSTLEN</name>
              <bitOffset>1</bitOffset>
              <bitWidth>4</bitWidth>
            </field>
            <field>
              <name>DMAEN</name>
              <bitOffset>5</bitOffset>
              <bitWidth>1</bitWidth>
            </field>
            <field>
              <name>TXFELVL</name>
              <bitOffset>7</bitOffset>
              <bitWidth>1</bitWidth>
            </field>
            <field>
              <name>PTXFELVL</name>
              <bitOffset>8</bitOffset>
              <bitWidth>1</bitWidth>
            </field>
          </fields>
        </register>
        <register>
          <name>GUSBCFG</name>
          <addressOffset>0xc</addressOffset>
          <size>0x20</size>
          <fields>
            <field>
              <name>TOCAL</name>
              <bitOffset>0</bitOffset>
              <bitWidth>3</bitWidth>
            </field>
            <field>
              <name>PHYSEL</name>
              <bitOffset>6</bitOffset>
              <bitWidth>1</bitWidth>
            </field>
            <field>
              <name>SRPCAP</name>
              <bitOffset>8</bitOffset>
              <bitWidth>1</bitWidth>
            </field>
            <field>
              <name>HNPCAP</name>
              <bitOffset>9</bitOffset>
              <bitWidth>1</bitWidth>
            </field>
            <field>
              <name>TRDT</name>
              <bitOffset>10</bitOffset>
              <bitWidth>4</bitWidth>
            </field>
            <field>
              <name>PHYLPCS</name>
              <bitOffset>15</bitOffset>
              <bitWidth>1</bitWidth>
            </field>
            <field>
              <name>ULPIFSLS</name>
              <bitOffset>17</bitOffset>
              <bitWidth>1</bitWidth>
            </field>
            <field>
              <name>ULPIAR</name>
              <bitOffset>18</bitOffset>
              <bitWidth>1</bitWidth>
            </field>
            <field>
              <name>ULPICSM</name>
              <bitOffset>19</bitOffset>
              <bitWidth>1</bitWidth>
            </field>
            <field>
              <name>ULPIEVBUSD</name>
              <bitOffset>20</bitOffset>
              <bitWidth>1</bitWidth>
            </field>
            <field>
              <name>ULPIEVBUSI</name>
              <bitOffset>21</bitOffset>
              <bitWidth>1</bitWidth>
            </field>
            <field>
              <name>TSDPS</name>
              <bitOffset>22</bitOffset>
              <bitWidth>1</bitWidth>
            </field>
            <field>
              <name>PCCI</name>
              <bitOffset>23</bitOffset>
              <bitWidth>1</bitWidth>
            </field>
            <field>
              <name>PTCI</name>
              <bitOffset>24</bitOffset>
              <bitWidth>1</bitWidth>
            </field>
            <field>
              <name>ULPIIPD</name>
              <bitOffset>25</bitOffset>
              <bitWidth>1</bitWidth>
            </field>
            <field>
              <name>FHMOD</name>
              <bitOffset>29</bitOffset>
              <bitWidth>1</bitWidth>
            </field>
            <field>
              <name>FDMOD</name>
              <bitOffset>30</bitOffset>
              <bitWidth>1</bitWidth>
            </field>
            <field>
              <name>CTXPKT</name>
              <bitOffset>31</bitOffset>
              <bitWidth>1</bitWidth>
            </field>
          </fields>
        </register>
        <register>
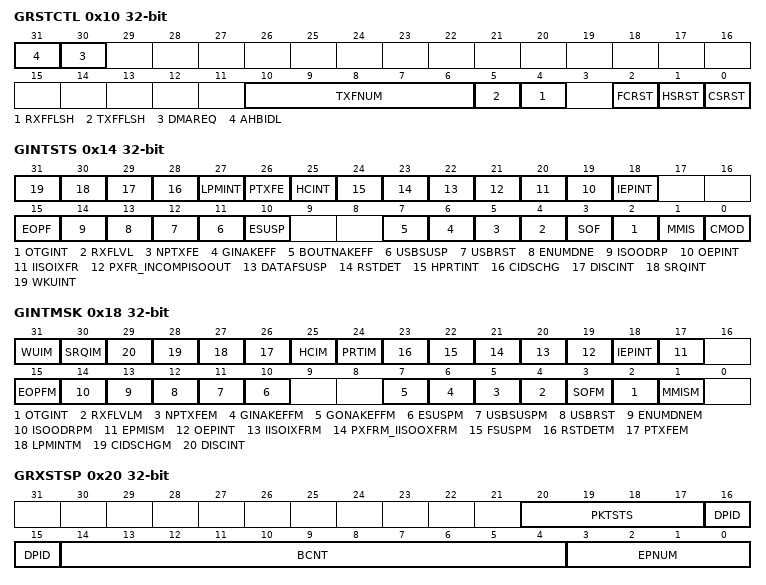
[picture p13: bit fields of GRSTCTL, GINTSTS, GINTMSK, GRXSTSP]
          <name>GRSTCTL</name>
          <addressOffset>0x10</addressOffset>
          <size>0x20</size>
          <fields>
            <field>
              <name>CSRST</name>
              <bitOffset>0</bitOffset>
              <bitWidth>1</bitWidth>
            </field>
            <field>
              <name>HSRST</name>
              <bitOffset>1</bitOffset>
              <bitWidth>1</bitWidth>
            </field>
            <field>
              <name>FCRST</name>
              <bitOffset>2</bitOffset>
              <bitWidth>1</bitWidth>
            </field>
            <field>
              <name>RXFFLSH</name>
              <bitOffset>4</bitOffset>
              <bitWidth>1</bitWidth>
            </field>
            <field>
              <name>TXFFLSH</name>
              <bitOffset>5</bitOffset>
              <bitWidth>1</bitWidth>
            </field>
            <field>
              <name>TXFNUM</name>
              <bitOffset>6</bitOffset>
              <bitWidth>5</bitWidth>
            </field>
            <field>
              <name>DMAREQ</name>
              <bitOffset>30</bitOffset>
              <bitWidth>1</bitWidth>
            </field>
            <field>
              <name>AHBIDL</name>
              <bitOffset>31</bitOffset>
              <bitWidth>1</bitWidth>
            </field>
          </fields>
        </register>
        <register>
          <name>GINTSTS</name>
          <addressOffset>0x14</addressOffset>
          <size>0x20</size>
          <fields>
            <field>
              <name>CMOD</name>
              <bitOffset>0</bitOffset>
              <bitWidth>1</bitWidth>
            </field>
            <field>
              <name>MMIS</name>
              <bitOffset>1</bitOffset>
              <bitWidth>1</bitWidth>
            </field>
            <field>
              <name>OTGINT</name>
              <bitOffset>2</bitOffset>
              <bitWidth>1</bitWidth>
            </field>
            <field>
              <name>SOF</name>
              <bitOffset>3</bitOffset>
              <bitWidth>1</bitWidth>
            </field>
            <field>
              <name>RXFLVL</name>
              <bitOffset>4</bitOffset>
              <bitWidth>1</bitWidth>
            </field>
            <field>
              <name>NPTXFE</name>
              <bitOffset>5</bitOffset>
              <bitWidth>1</bitWidth>
            </field>
            <field>
              <name>GINAKEFF</name>
              <bitOffset>6</bitOffset>
              <bitWidth>1</bitWidth>
            </field>
            <field>
              <name>BOUTNAKEFF</name>
              <bitOffset>7</bitOffset>
              <bitWidth>1</bitWidth>
            </field>
            <field>
              <name>ESUSP</name>
              <bitOffset>10</bitOffset>
              <bitWidth>1</bitWidth>
            </field>
            <field>
              <name>USBSUSP</name>
              <bitOffset>11</bitOffset>
              <bitWidth>1</bitWidth>
            </field>
            <field>
              <name>USBRST</name>
              <bitOffset>12</bitOffset>
              <bitWidth>1</bitWidth>
            </field>
            <field>
              <name>ENUMDNE</name>
              <bitOffset>13</bitOffset>
              <bitWidth>1</bitWidth>
            </field>
            <field>
              <name>ISOODRP</name>
              <bitOffset>14</bitOffset>
              <bitWidth>1</bitWidth>
            </field>
            <field>
              <name>EOPF</name>
              <bitOffset>15</bitOffset>
              <bitWidth>1</bitWidth>
            </field>
            <field>
              <name>IEPINT</name>
              <bitOffset>18</bitOffset>
              <bitWidth>1</bitWidth>
            </field>
            <field>
              <name>OEPINT</name>
              <bitOffset>19</bitOffset>
              <bitWidth>1</bitWidth>
            </field>
            <field>
              <name>IISOIXFR</name>
              <bitOffset>20</bitOffset>
              <bitWidth>1</bitWidth>
            </field>
            <field>
              <name>PXFR_INCOMPISOOUT</name>
              <bitOffset>21</bitOffset>
              <bitWidth>1</bitWidth>
            </field>
            <field>
              <name>DATAFSUSP</name>
              <bitOffset>22</bitOffset>
              <bitWidth>1</bitWidth>
            </field>
            <field>
              <name>RSTDET</name>
              <bitOffset>23</bitOffset>
              <bitWidth>1</bitWidth>
            </field>
            <field>
              <name>HPRTINT</name>
              <bitOffset>24</bitOffset>
              <bitWidth>1</bitWidth>
            </field>
            <field>
              <name>HCINT</name>
              <bitOffset>25</bitOffset>
              <bitWidth>1</bitWidth>
            </field>
            <field>
              <name>PTXFE</name>
              <bitOffset>26</bitOffset>
              <bitWidth>1</bitWidth>
            </field>
            <field>
              <name>LPMINT</name>
              <bitOffset>27</bitOffset>
              <bitWidth>1</bitWidth>
            </field>
            <field>
              <name>CIDSCHG</name>
              <bitOffset>28</bitOffset>
              <bitWidth>1</bitWidth>
            </field>
            <field>
              <name>DISCINT</name>
              <bitOffset>29</bitOffset>
              <bitWidth>1</bitWidth>
            </field>
            <field>
              <name>SRQINT</name>
              <bitOffset>30</bitOffset>
              <bitWidth>1</bitWidth>
            </field>
            <field>
              <name>WKUINT</name>
              <bitOffset>31</bitOffset>
              <bitWidth>1</bitWidth>
            </field>
          </fields>
        </register>
        <register>
          <name>GINTMSK</name>
          <addressOffset>0x18</addressOffset>
          <size>0x20</size>
          <fields>
            <field>
              <name>MMISM</name>
              <bitOffset>1</bitOffset>
              <bitWidth>1</bitWidth>
            </field>
            <field>
              <name>OTGINT</name>
              <bitOffset>2</bitOffset>
              <bitWidth>1</bitWidth>
            </field>
            <field>
              <name>SOFM</name>
              <bitOffset>3</bitOffset>
              <bitWidth>1</bitWidth>
            </field>
            <field>
              <name>RXFLVLM</name>
              <bitOffset>4</bitOffset>
              <bitWidth>1</bitWidth>
            </field>
            <field>
              <name>NPTXFEM</name>
              <bitOffset>5</bitOffset>
              <bitWidth>1</bitWidth>
            </field>
            <field>
              <name>GINAKEFFM</name>
              <bitOffset>6</bitOffset>
              <bitWidth>1</bitWidth>
            </field>
            <field>
              <name>GONAKEFFM</name>
              <bitOffset>7</bitOffset>
              <bitWidth>1</bitWidth>
            </field>
            <field>
              <name>ESUSPM</name>
              <bitOffset>10</bitOffset>
              <bitWidth>1</bitWidth>
            </field>
            <field>
              <name>USBSUSPM</name>
              <bitOffset>11</bitOffset>
              <bitWidth>1</bitWidth>
            </field>
            <field>
              <name>USBRST</name>
              <bitOffset>12</bitOffset>
              <bitWidth>1</bitWidth>
            </field>
            <field>
              <name>ENUMDNEM</name>
              <bitOffset>13</bitOffset>
              <bitWidth>1</bitWidth>
            </field>
            <field>
              <name>ISOODRPM</name>
              <bitOffset>14</bitOffset>
              <bitWidth>1</bitWidth>
            </field>
            <field>
              <name>EOPFM</name>
              <bitOffset>15</bitOffset>
              <bitWidth>1</bitWidth>
            </field>
            <field>
              <name>EPMISM</name>
              <bitOffset>17</bitOffset>
              <bitWidth>1</bitWidth>
            </field>
            <field>
              <name>IEPINT</name>
              <bitOffset>18</bitOffset>
              <bitWidth>1</bitWidth>
            </field>
            <field>
              <name>OEPINT</name>
              <bitOffset>19</bitOffset>
              <bitWidth>1</bitWidth>
            </field>
            <field>
              <name>IISOIXFRM</name>
              <bitOffset>20</bitOffset>
              <bitWidth>1</bitWidth>
            </field>
            <field>
              <name>PXFRM_IISOOXFRM</name>
              <bitOffset>21</bitOffset>
              <bitWidth>1</bitWidth>
            </field>
            <field>
              <name>FSUSPM</name>
              <bitOffset>22</bitOffset>
              <bitWidth>1</bitWidth>
            </field>
            <field>
              <name>RSTDETM</name>
              <bitOffset>23</bitOffset>
              <bitWidth>1</bitWidth>
            </field>
            <field>
              <name>PRTIM</name>
              <bitOffset>24</bitOffset>
              <bitWidth>1</bitWidth>
            </field>
            <field>
              <name>HCIM</name>
              <bitOffset>25</bitOffset>
              <bitWidth>1</bitWidth>
            </field>
            <field>
              <name>PTXFEM</name>
              <bitOffset>26</bitOffset>
              <bitWidth>1</bitWidth>
            </field>
            <field>
              <name>LPMINTM</name>
              <bitOffset>27</bitOffset>
              <bitWidth>1</bitWidth>
            </field>
            <field>
              <name>CIDSCHGM</name>
              <bitOffset>28</bitOffset>
              <bitWidth>1</bitWidth>
            </field>
            <field>
              <name>DISCINT</name>
              <bitOffset>29</bitOffset>
              <bitWidth>1</bitWidth>
            </field>
            <field>
              <name>SRQIM</name>
              <bitOffset>30</bitOffset>
              <bitWidth>1</bitWidth>
            </field>
            <field>
              <name>WUIM</name>
              <bitOffset>31</bitOffset>
              <bitWidth>1</bitWidth>
            </field>
          </fields>
        </register>
        <register>
          <name>GRXSTSR</name>
          <addressOffset>0x1c</addressOffset>
          <size>0x20</size>
        </register>
        <register>
          <name>GRXSTSP</name>
          <addressOffset>0x20</addressOffset>
          <size>0x20</size>
          <fields>
            <field>
              <name>EPNUM</name>
              <bitOffset>0</bitOffset>
              <bitWidth>4</bitWidth>
            </field>
            <field>
              <name>BCNT</name>
              <bitOffset>4</bitOffset>
              <bitWidth>11</bitWidth>
            </field>
            <field>
              <name>DPID</name>
              <bitOffset>15</bitOffset>
              <bitWidth>2</bitWidth>
            </field>
            <field>
              <name>PKTSTS</name>
              <bitOffset>17</bitOffset>
              <bitWidth>4</bitWidth>
            </field>
          </fields>
        </register>
        <register>
          <name>GRXFSIZ</name>
          <addressOffset>0x24</addressOffset>
          <size>0x20</size>
          <fields>
            <field>
              <name>RXFD</name>
              <bitOffset>0</bitOffset>
              <bitWidth>16</bitWidth>
            </field>
          </fields>
        </register>
        <register>
          <name>DIEPTXF0_HNPTXFSIZ</name>
          <addressOffset>0x28</addressOffset>
          <size>0x20</size>
        </register>
        <register>
          <name>HNPTXSTS</name>
          <addressOffset>0x2c</addressOffset>
          <size>0x20</size>
        </register>
        <register>
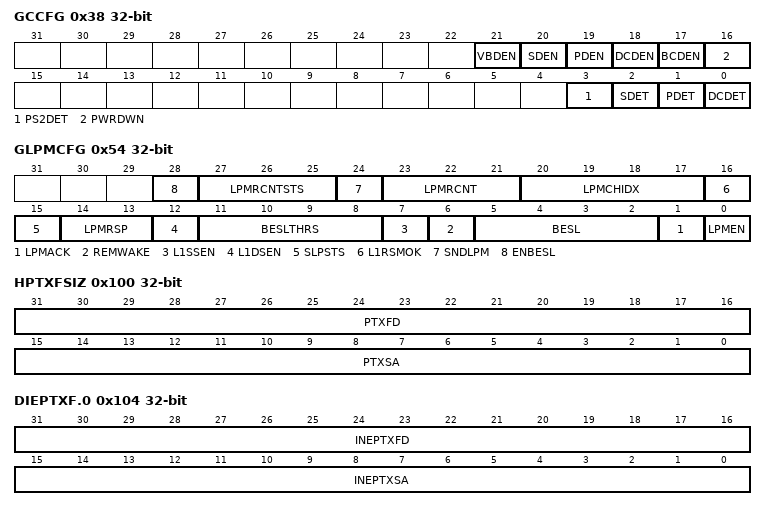
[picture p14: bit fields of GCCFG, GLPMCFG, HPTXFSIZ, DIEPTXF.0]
          <name>GCCFG</name>
          <addressOffset>0x38</addressOffset>
          <size>0x20</size>
          <fields>
            <field>
              <name>DCDET</name>
              <bitOffset>0</bitOffset>
              <bitWidth>1</bitWidth>
            </field>
            <field>
              <name>PDET</name>
              <bitOffset>1</bitOffset>
              <bitWidth>1</bitWidth>
            </field>
            <field>
              <name>SDET</name>
              <bitOffset>2</bitOffset>
              <bitWidth>1</bitWidth>
            </field>
            <field>
              <name>PS2DET</name>
              <bitOffset>3</bitOffset>
              <bitWidth>1</bitWidth>
            </field>
            <field>
              <name>PWRDWN</name>
              <bitOffset>16</bitOffset>
              <bitWidth>1</bitWidth>
            </field>
            <field>
              <name>BCDEN</name>
              <bitOffset>17</bitOffset>
              <bitWidth>1</bitWidth>
            </field>
            <field>
              <name>DCDEN</name>
              <bitOffset>18</bitOffset>
              <bitWidth>1</bitWidth>
            </field>
            <field>
              <name>PDEN</name>
              <bitOffset>19</bitOffset>
              <bitWidth>1</bitWidth>
            </field>
            <field>
              <name>SDEN</name>
              <bitOffset>20</bitOffset>
              <bitWidth>1</bitWidth>
            </field>
            <field>
              <name>VBDEN</name>
              <bitOffset>21</bitOffset>
              <bitWidth>1</bitWidth>
            </field>
          </fields>
        </register>
        <register>
          <name>CID</name>
          <addressOffset>0x3c</addressOffset>
          <size>0x20</size>
          <fields>
            <field>
              <name>PRODUCT_ID</name>
              <bitOffset>0</bitOffset>
              <bitWidth>32</bitWidth>
            </field>
          </fields>
        </register>
        <register>
          <name>GHWCFG3</name>
          <addressOffset>0x4c</addressOffset>
          <size>0x20</size>
        </register>
        <register>
          <name>GLPMCFG</name>
          <addressOffset>0x54</addressOffset>
          <size>0x20</size>
          <fields>
            <field>
              <name>LPMEN</name>
              <bitOffset>0</bitOffset>
              <bitWidth>1</bitWidth>
            </field>
            <field>
              <name>LPMACK</name>
              <bitOffset>1</bitOffset>
              <bitWidth>1</bitWidth>
            </field>
            <field>
              <name>BESL</name>
              <bitOffset>2</bitOffset>
              <bitWidth>4</bitWidth>
            </field>
            <field>
              <name>REMWAKE</name>
              <bitOffset>6</bitOffset>
              <bitWidth>1</bitWidth>
            </field>
            <field>
              <name>L1SSEN</name>
              <bitOffset>7</bitOffset>
              <bitWidth>1</bitWidth>
            </field>
            <field>
              <name>BESLTHRS</name>
              <bitOffset>8</bitOffset>
              <bitWidth>4</bitWidth>
            </field>
            <field>
              <name>L1DSEN</name>
              <bitOffset>12</bitOffset>
              <bitWidth>1</bitWidth>
            </field>
            <field>
              <name>LPMRSP</name>
              <bitOffset>13</bitOffset>
              <bitWidth>2</bitWidth>
            </field>
            <field>
              <name>SLPSTS</name>
              <bitOffset>15</bitOffset>
              <bitWidth>1</bitWidth>
            </field>
            <field>
              <name>L1RSMOK</name>
              <bitOffset>16</bitOffset>
              <bitWidth>1</bitWidth>
            </field>
            <field>
              <name>LPMCHIDX</name>
              <bitOffset>17</bitOffset>
              <bitWidth>4</bitWidth>
            </field>
            <field>
              <name>LPMRCNT</name>
              <bitOffset>21</bitOffset>
              <bitWidth>3</bitWidth>
            </field>
            <field>
              <name>SNDLPM</name>
              <bitOffset>24</bitOffset>
              <bitWidth>1</bitWidth>
            </field>
            <field>
              <name>LPMRCNTSTS</name>
              <bitOffset>25</bitOffset>
              <bitWidth>3</bitWidth>
            </field>
            <field>
              <name>ENBESL</name>
              <bitOffset>28</bitOffset>
              <bitWidth>1</bitWidth>
            </field>
          </fields>
        </register>
        <register>
          <name>GDFIFOCFG</name>
          <addressOffset>0x5c</addressOffset>
          <size>0x20</size>
        </register>
        <register>
          <name>HPTXFSIZ</name>
          <addressOffset>0x100</addressOffset>
          <size>0x20</size>
          <fields>
            <field>
              <name>PTXSA</name>
              <bitOffset>0</bitOffset>
              <bitWidth>16</bitWidth>
            </field>
            <field>
              <name>PTXFD</name>
              <bitOffset>16</bitOffset>
              <bitWidth>16</bitWidth>
            </field>
          </fields>
        </register>
        <register>
          <name>DIEPTXF.0</name>
          <addressOffset>0x104</addressOffset>
          <size>0x20</size>
          <fields>
            <field>
              <name>INEPTXSA</name>
              <bitOffset>0</bitOffset>
              <bitWidth>16</bitWidth>
            </field>
            <field>
              <name>INEPTXFD</name>
              <bitOffset>16</bitOffset>
              <bitWidth>16</bitWidth>
            </field>
          </fields>
        </register>
        <register>
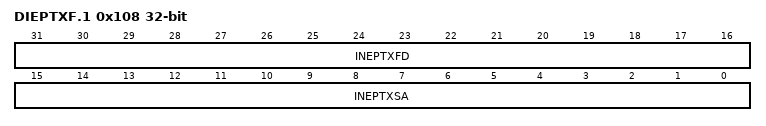
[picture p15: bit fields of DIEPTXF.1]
          <name>DIEPTXF.1</name>
          <addressOffset>0x108</addressOffset>
          <size>0x20</size>
          <fields>
            <field>
              <name>INEPTXSA</name>
              <bitOffset>0</bitOffset>
              <bitWidth>16</bitWidth>
            </field>
            <field>
              <name>INEPTXFD</name>
              <bitOffset>16</bitOffset>
              <bitWidth>16</bitWidth>
            </field>
          </fields>
        </register>
        <register>
          <name>DIEPTXF.2</name>
          <addressOffset>0x10c</addressOffset>
          <size>0x20</size>
          <fields>
            <field>
              <name>INEPTXSA</name>
              <bitOffset>0</bitOffset>
              <bitWidth>16</bitWidth>
            </field>
            <field>
              <name>INEPTXFD</name>
              <bitOffset>16</bitOffset>
              <bitWidth>16</bitWidth>
            </field>
          </fields>
        </register>
        <register>
          <name>DIEPTXF.3</name>
          <addressOffset>0x110</addressOffset>
          <size>0x20</size>
          <fields>
            <field>
              <name>INEPTXSA</name>
              <bitOffset>0</bitOffset>
              <bitWidth>16</bitWidth>
            </field>
            <field>
              <name>INEPTXFD</name>
              <bitOffset>16</bitOffset>
              <bitWidth>16</bitWidth>
            </field>
          </fields>
        </register>
        <register>
          <name>DIEPTXF.4</name>
          <addressOffset>0x114</addressOffset>
          <size>0x20</size>
          <fields>
            <field>
              <name>INEPTXSA</name>
              <bitOffset>0</bitOffset>
              <bitWidth>16</bitWidth>
            </field>
            <field>
              <name>INEPTXFD</name>
              <bitOffset>16</bitOffset>
              <bitWidth>16</bitWidth>
            </field>
          </fields>
        </register>
        <register>
          <name>DIEPTXF.5</name>
          <addressOffset>0x118</addressOffset>
          <size>0x20</size>
          <fields>
            <field>
              <name>INEPTXSA</name>
              <bitOffset>0</bitOffset>
              <bitWidth>16</bitWidth>
            </field>
            <field>
              <name>INEPTXFD</name>
              <bitOffset>16</bitOffset>
              <bitWidth>16</bitWidth>
            </field>
          </fields>
        </register>
        <register>
          <name>DIEPTXF.6</name>
          <addressOffset>0x11c</addressOffset>
          <size>0x20</size>
          <fields>
            <field>
              <name>INEPTXSA</name>
              <bitOffset>0</bitOffset>
              <bitWidth>16</bitWidth>
            </field>
            <field>
              <name>INEPTXFD</name>
              <bitOffset>16</bitOffset>
              <bitWidth>16</bitWidth>
            </field>
          </fields>
        </register>
        <register>
          <name>DIEPTXF.7</name>
          <addressOffset>0x120</addressOffset>
          <size>0x20</size>
          <fields>
            <field>
              <name>INEPTXSA</name>
              <bitOffset>0</bitOffset>
              <bitWidth>16</bitWidth>
            </field>
            <field>
              <name>INEPTXFD</name>
              <bitOffset>16</bitOffset>
              <bitWidth>16</bitWidth>
            </field>
          </fields>
        </register>
        <register>
          <name>DIEPTXF.8</name>
          <addressOffset>0x124</addressOffset>
          <size>0x20</size>
          <fields>
            <field>
              <name>INEPTXSA</name>
              <bitOffset>0</bitOffset>
              <bitWidth>16</bitWidth>
            </field>
            <field>
              <name>INEPTXFD</name>
              <bitOffset>16</bitOffset>
              <bitWidth>16</bitWidth>
            </field>
          </fields>
        </register>
        <register>
          <name>DIEPTXF.9</name>
          <addressOffset>0x128</addressOffset>
          <size>0x20</size>
          <fields>
            <field>
              <name>INEPTXSA</name>
              <bitOffset>0</bitOffset>
              <bitWidth>16</bitWidth>
            </field>
            <field>
              <name>INEPTXFD</name>
              <bitOffset>16</bitOffset>
              <bitWidth>16</bitWidth>
            </field>
          </fields>
        </register>
        <register>
          <name>DIEPTXF.10</name>
          <addressOffset>0x12c</addressOffset>
          <size>0x20</size>
          <fields>
            <field>
              <name>INEPTXSA</name>
              <bitOffset>0</bitOffset>
              <bitWidth>16</bitWidth>
            </field>
            <field>
              <name>INEPTXFD</name>
              <bitOffset>16</bitOffset>
              <bitWidth>16</bitWidth>
            </field>
          </fields>
        </register>
        <register>
          <name>DIEPTXF.11</name>
          <addressOffset>0x130</addressOffset>
          <size>0x20</size>
          <fields>
            <field>
              <name>INEPTXSA</name>
              <bitOffset>0</bitOffset>
              <bitWidth>16</bitWidth>
            </field>
            <field>
              <name>INEPTXFD</name>
              <bitOffset>16</bitOffset>
              <bitWidth>16</bitWidth>
            </field>
          </fields>
        </register>
        <register>
          <name>DIEPTXF.12</name>
          <addressOffset>0x134</addressOffset>
          <size>0x20</size>
          <fields>
            <field>
              <name>INEPTXSA</name>
              <bitOffset>0</bitOffset>
              <bitWidth>16</bitWidth>
            </field>
            <field>
              <name>INEPTXFD</name>
              <bitOffset>16</bitOffset>
              <bitWidth>16</bitWidth>
            </field>
          </fields>
        </register>
        <register>
          <name>DIEPTXF.13</name>
          <addressOffset>0x138</addressOffset>
          <size>0x20</size>
          <fields>
            <field>
              <name>INEPTXSA</name>
              <bitOffset>0</bitOffset>
              <bitWidth>16</bitWidth>
            </field>
            <field>
              <name>INEPTXFD</name>
              <bitOffset>16</bitOffset>
              <bitWidth>16</bitWidth>
            </field>
          </fields>
        </register>
        <register>
          <name>DIEPTXF.14</name>
          <addressOffset>0x13c</addressOffset>
          <size>0x20</size>
          <fields>
            <field>
              <name>INEPTXSA</name>
              <bitOffset>0</bitOffset>
              <bitWidth>16</bitWidth>
            </field>
            <field>
              <name>INEPTXFD</name>
              <bitOffset>16</bitOffset>
              <bitWidth>16</bitWidth>
            </field>
          </fields>
        </register>
      </registers>
    </peripheral>
    <peripheral>
      <name>RNG</name>
      <baseAddress>0x50060800</baseAddress>
      <registers>
        <register>
          <name>CR</name>
          <addressOffset>0x0</addressOffset>
          <size>0x20</size>
          <fields>
            <field>
              <name>RNGEN</name>
              <bitOffset>2</bitOffset>
              <bitWidth>1</bitWidth>
            </field>
            <field>
              <name>IE</name>
              <bitOffset>3</bitOffset>
              <bitWidth>1</bitWidth>
            </field>
          </fields>
        </register>
        <register>
          <name>SR</name>
          <addressOffset>0x4</addressOffset>
          <size>0x20</size>
          <fields>
            <field>
              <name>DRDY</name>
              <bitOffset>0</bitOffset>
              <bitWidth>1</bitWidth>
            </field>
            <field>
              <name>CECS</name>
              <bitOffset>1</bitOffset>
              <bitWidth>1</bitWidth>
            </field>
            <field>
              <name>SECS</name>
              <bitOffset>2</bitOffset>
              <bitWidth>1</bitWidth>
            </field>
            <field>
              <name>CEIS</name>
              <bitOffset>5</bitOffset>
              <bitWidth>1</bitWidth>
            </field>
            <field>
              <name>SEIS</name>
              <bitOffset>6</bitOffset>
              <bitWidth>1</bitWidth>
            </field>
          </fields>
        </register>
        <register>
          <name>DR</name>
          <addressOffset>0x8</addressOffset>
          <size>0x20</size>
        </register>
      </registers>
    </peripheral>
    <peripheral>
      <name>DBGMCU</name>
      <baseAddress>0xe0042000</baseAddress>
      <registers>
        <register>
          <name>IDCODE</name>
          <addressOffset>0x0</addressOffset>
          <size>0x20</size>
          <fields>
            <field>
              <name>DEV_ID</name>
              <bitOffset>0</bitOffset>
              <bitWidth>12</bitWidth>
            </field>
            <field>
              <name>REV_ID</name>
              <bitOffset>16</bitOffset>
              <bitWidth>16</bitWidth>
            </field>
          </fields>
        </register>
        <register>
          <name>CR</name>
          <addressOffset>0x4</addressOffset>
          <size>0x20</size>
          <fields>
            <field>
              <name>DBG_SLEEP</name>
              <bitOffset>0</bitOffset>
              <bitWidth>1</bitWidth>
            </field>
            <field>
              <name>DBG_STOP</name>
              <bitOffset>1</bitOffset>
              <bitWidth>1</bitWidth>
            </field>
            <field>
              <name>DBG_STANDBY</name>
              <bitOffset>2</bitOffset>
              <bitWidth>1</bitWidth>
            </field>
            <field>
              <name>TRACE_IOEN</name>
              <bitOffset>5</bitOffset>
              <bitWidth>1</bitWidth>
            </field>
            <field>
              <name>TRACE_MODE</name>
              <bitOffset>6</bitOffset>
              <bitWidth>2</bitWidth>
            </field>
          </fields>
        </register>
        <register>
          <name>APB1FZ</name>
          <addressOffset>0x8</addressOffset>
          <size>0x20</size>
          <fields>
            <field>
              <name>DBG_TIM2_STOP</name>
              <bitOffset>0</bitOffset>
              <bitWidth>1</bitWidth>
            </field>
            <field>
              <name>DBG_TIM3_STOP</name>
              <bitOffset>1</bitOffset>
              <bitWidth>1</bitWidth>
            </field>
            <field>
              <name>DBG_TIM4_STOP</name>
              <bitOffset>2</bitOffset>
              <bitWidth>1</bitWidth>
            </field>
            <field>
              <name>DBG_TIM5_STOP</name>
              <bitOffset>3</bitOffset>
              <bitWidth>1</bitWidth>
            </field>
            <field>
              <name>DBG_TIM6_STOP</name>
              <bitOffset>4</bitOffset>
              <bitWidth>1</bitWidth>
            </field>
            <field>
              <name>DBG_TIM7_STOP</name>
              <bitOffset>5</bitOffset>
              <bitWidth>1</bitWidth>
            </field>
            <field>
              <name>DBG_TIM12_STOP</name>
              <bitOffset>6</bitOffset>
              <bitWidth>1</bitWidth>
            </field>
            <field>
              <name>DBG_TIM13_STOP</name>
              <bitOffset>7</bitOffset>
              <bitWidth>1</bitWidth>
            </field>
            <field>
              <name>DBG_TIM14_STOP</name>
              <bitOffset>8</bitOffset>
              <bitWidth>1</bitWidth>
            </field>
            <field>
              <name>DBG_RTC_STOP</name>
              <bitOffset>10</bitOffset>
              <bitWidth>1</bitWidth>
            </field>
            <field>
              <name>DBG_WWDG_STOP</name>
              <bitOffset>11</bitOffset>
              <bitWidth>1</bitWidth>
            </field>
            <field>
              <name>DBG_IWDG_STOP</name>
              <bitOffset>12</bitOffset>
              <bitWidth>1</bitWidth>
            </field>
            <field>
              <name>DBG_I2C1_SMBUS_TIMEOUT</name>
              <bitOffset>21</bitOffset>
              <bitWidth>1</bitWidth>
            </field>
            <field>
              <name>DBG_I2C2_SMBUS_TIMEOUT</name>
              <bitOffset>22</bitOffset>
              <bitWidth>1</bitWidth>
            </field>
            <field>
              <name>DBG_I2C3_SMBUS_TIMEOUT</name>
              <bitOffset>23</bitOffset>
              <bitWidth>1</bitWidth>
            </field>
            <field>
              <name>DBG_I2C4_SMBUS_TIMEOUT</name>
              <bitOffset>24</bitOffset>
              <bitWidth>1</bitWidth>
            </field>
            <field>
              <name>DBG_CAN1_STOP</name>
              <bitOffset>25</bitOffset>
              <bitWidth>1</bitWidth>
            </field>
            <field>
              <name>DBG_CAN2_STOP</name>
              <bitOffset>26</bitOffset>
              <bitWidth>1</bitWidth>
            </field>
          </fields>
        </register>
        <register>
          <name>APB2FZ</name>
          <addressOffset>0xc</addressOffset>
          <size>0x20</size>
          <fields>
            <field>
              <name>DBG_TIM1_STOP</name>
              <bitOffset>0</bitOffset>
              <bitWidth>1</bitWidth>
            </field>
            <field>
              <name>DBG_TIM8_STOP</name>
              <bitOffset>1</bitOffset>
              <bitWidth>1</bitWidth>
            </field>
            <field>
              <name>DBG_TIM9_STOP</name>
              <bitOffset>16</bitOffset>
              <bitWidth>1</bitWidth>
            </field>
            <field>
              <name>DBG_TIM10_STOP</name>
              <bitOffset>17</bitOffset>
              <bitWidth>1</bitWidth>
            </field>
            <field>
              <name>DBG_TIM11_STOP</name>
              <bitOffset>18</bitOffset>
              <bitWidth>1</bitWidth>
            </field>
          </fields>
        </register>
      </registers>
    </peripheral>
  </peripherals>
</device>
